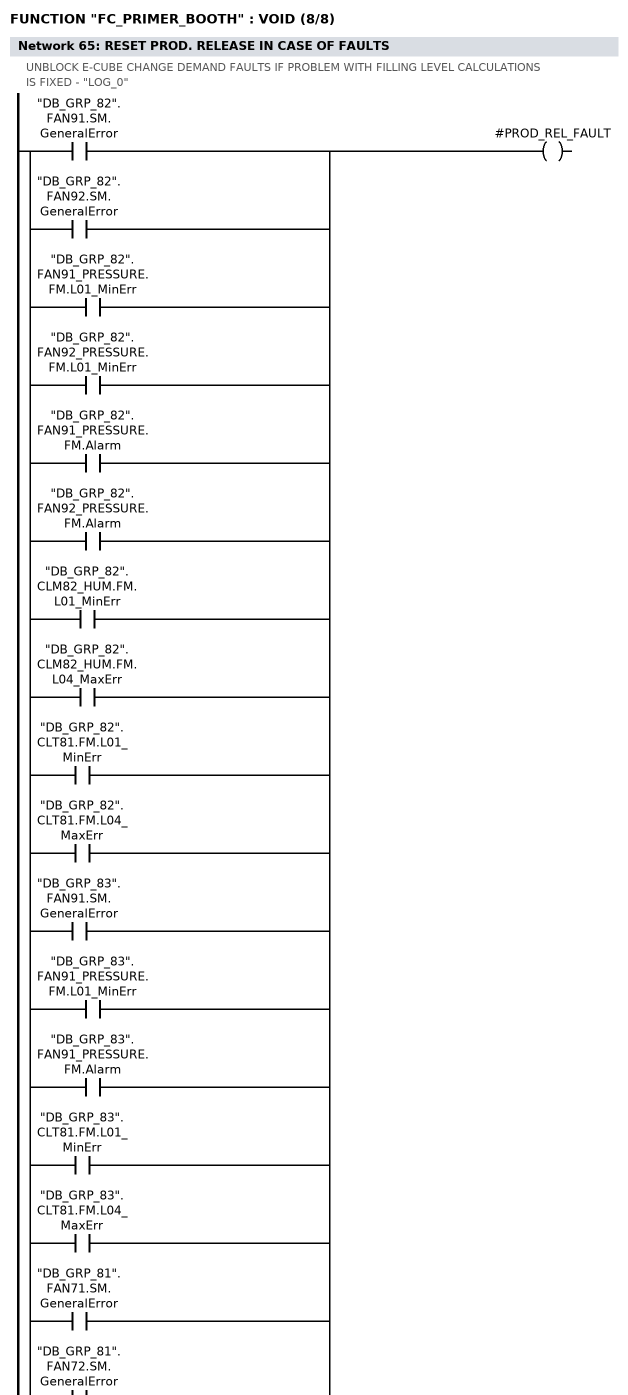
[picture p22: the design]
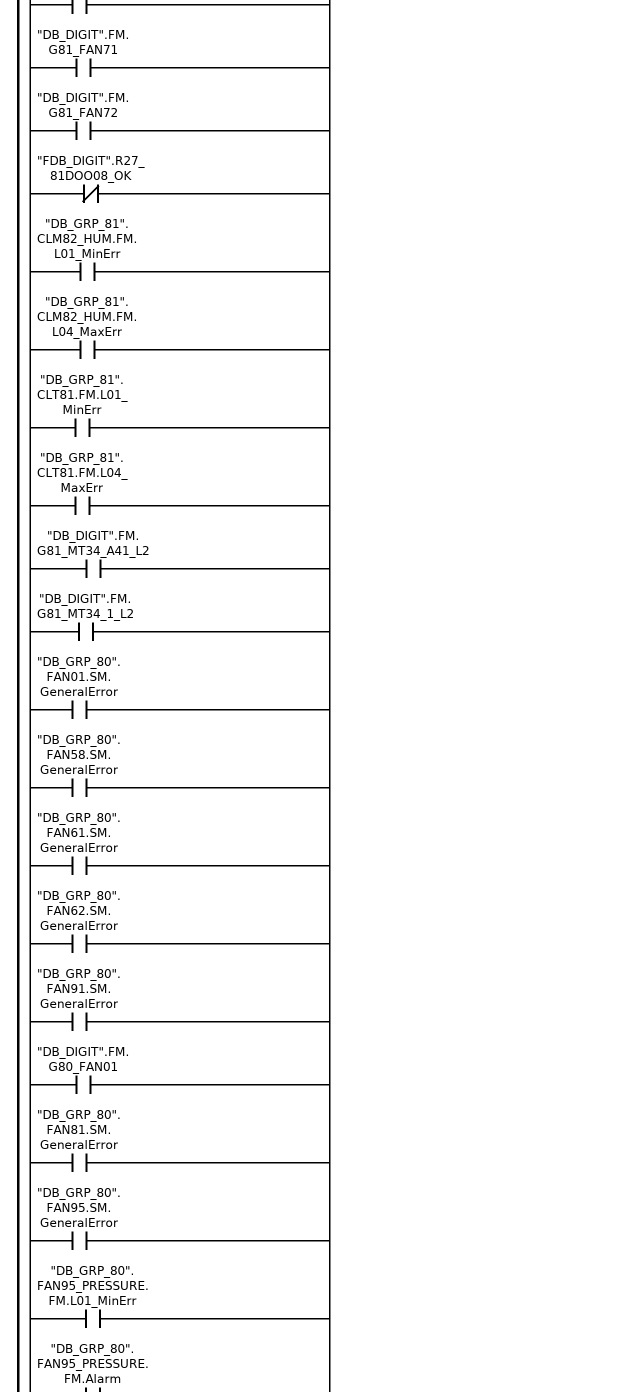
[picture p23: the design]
FUNCTION "FC_PRIMER_BOOTH" : VOID
TITLE =PRIMER BOOTH
{ S7_language := '9(1) Angielski (Stany Zjednoczone)  11.01.2022  09:45:15' }
VERSION : 0.1


VAR_TEMP
  ASU_PREHEAT_TIME_SP : S5TIME ;
  ROLL_UP_ENT_DOOR : BOOL ;
  PURGING_TIME_SP : S5TIME ;
  PROD_REL_CONV : BOOL ;
  PROD_REL_FAULT : BOOL ;
  PREPURGING_ON : BOOL ;
  FOLLOW_UP_PURGING_ON : BOOL ;
  F_UP_PRUGING_TIME_SP : S5TIME ;
  H_81CLM82_HUM_SWP : REAL ;
  H_81CLM82_DEHUM_SWP : REAL ;
  T_81CLT81_COOL_SWP : REAL ;
  T_81CLT81_HEAT_SWP : REAL ;
END_VAR
BEGIN
NETWORK
TITLE =PRIMER BOOTH ON
//********************************************************************************
//
//                         PRIMER BOOTH START / STOP
//
//********************************************************************************
//
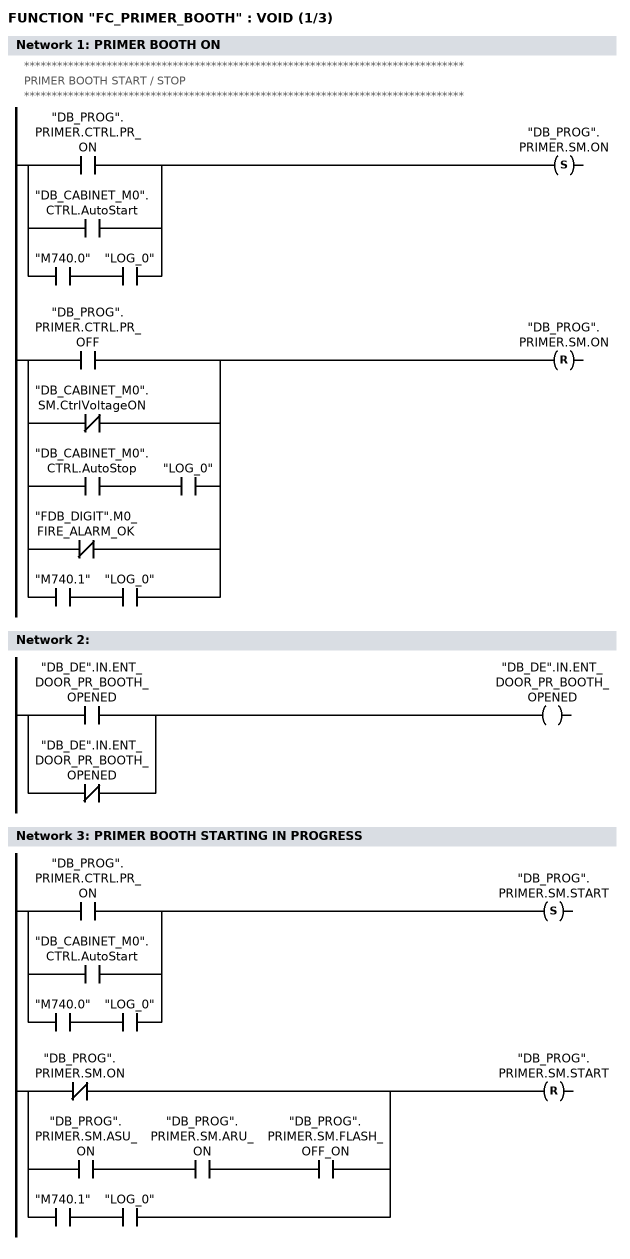
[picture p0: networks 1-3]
      U(    ;
      O     "DB_PROG".PRIMER.CTRL.PR_ON;
      O     "DB_CABINET_M0".CTRL.AutoStart;
      O     ;
      U     "M740.0";
      U     "LOG_0";
      )     ;
      S     "DB_PROG".PRIMER.SM.ON;
      U(    ;
      O     "DB_PROG".PRIMER.CTRL.PR_OFF;
      ON    "DB_CABINET_M0".SM.CtrlVoltageON;
      O     ;
      U     "DB_CABINET_M0".CTRL.AutoStop;
      U     "LOG_0";
      ON    "FDB_DIGIT".M0_FIRE_ALARM_OK;
      O     ;
      U     "M740.1";
      U     "LOG_0";
      )     ;
      R     "DB_PROG".PRIMER.SM.ON;
      NOP   0;
NETWORK
TITLE =

      O     "DB_DE".IN.ENT_DOOR_PR_BOOTH_OPENED;
      ON    "DB_DE".IN.ENT_DOOR_PR_BOOTH_OPENED;
      =     "DB_DE".IN.ENT_DOOR_PR_BOOTH_OPENED;
NETWORK
TITLE =PRIMER BOOTH STARTING IN PROGRESS

      U(    ;
      O     "DB_PROG".PRIMER.CTRL.PR_ON;
      O     "DB_CABINET_M0".CTRL.AutoStart;
      O     ;
      U     "M740.0";
      U     "LOG_0";
      )     ;
      S     "DB_PROG".PRIMER.SM.START;
      U(    ;
      ON    "DB_PROG".PRIMER.SM.ON;
      O     ;
      U     "DB_PROG".PRIMER.SM.ASU_ON;
      U     "DB_PROG".PRIMER.SM.ARU_ON;
      U     "DB_PROG".PRIMER.SM.FLASH_OFF_ON;
      O     ;
      U     "M740.1";
      U     "LOG_0";
      )     ;
      R     "DB_PROG".PRIMER.SM.START;
      NOP   0;
NETWORK
TITLE =PRIMER BOOTH STOPPING IN PROGRESS

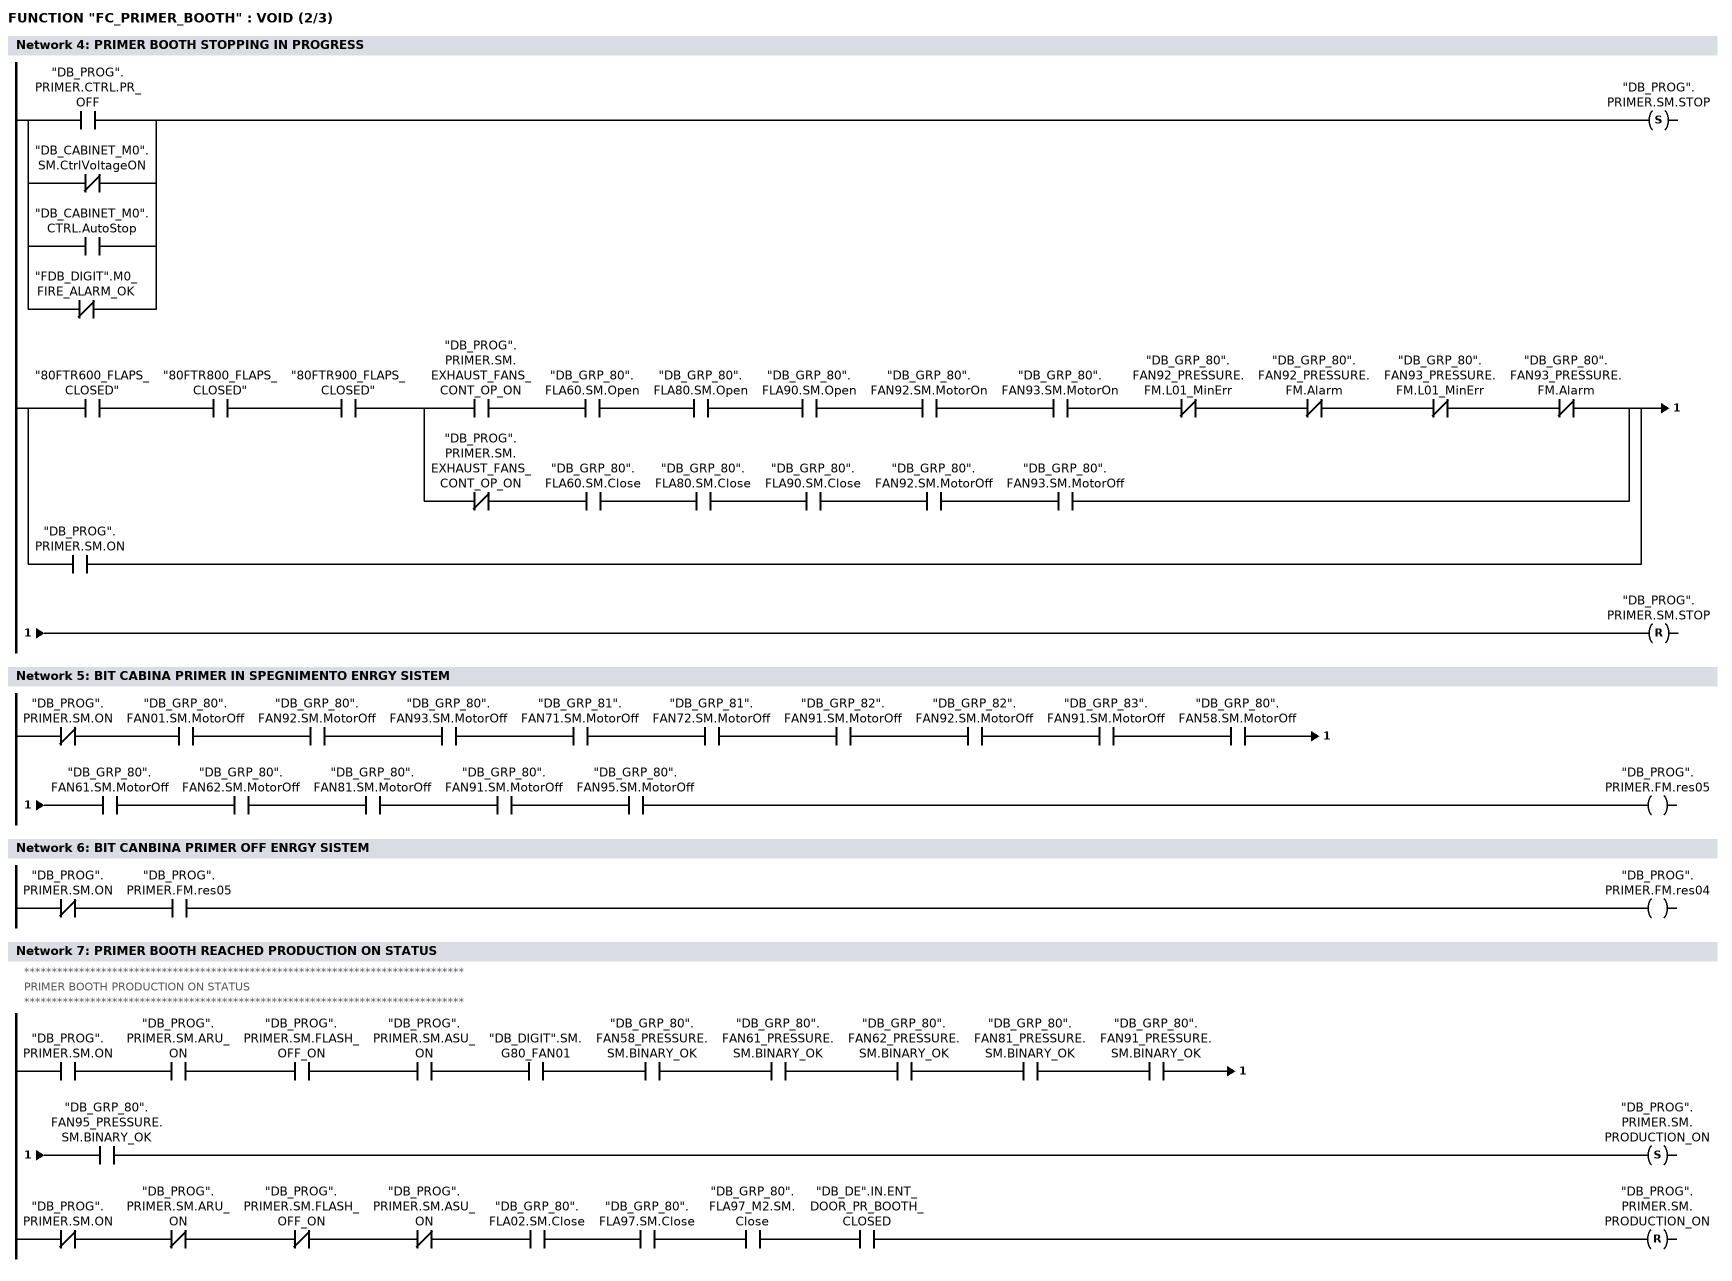
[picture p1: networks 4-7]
      U(    ;
      O     "DB_PROG".PRIMER.CTRL.PR_OFF;
      ON    "DB_CABINET_M0".SM.CtrlVoltageON;
      O     "DB_CABINET_M0".CTRL.AutoStop;
      ON    "FDB_DIGIT".M0_FIRE_ALARM_OK;
      )     ;
      S     "DB_PROG".PRIMER.SM.STOP;
      U(    ;
      U     "80FTR600_FLAPS_CLOSED";
      U     "80FTR800_FLAPS_CLOSED";
      U     "80FTR900_FLAPS_CLOSED";
      U(    ;
      U     "DB_PROG".PRIMER.SM.EXHAUST_FANS_CONT_OP_ON;
      U     "DB_GRP_80".FLA60.SM.Open;
      U     "DB_GRP_80".FLA80.SM.Open;
      U     "DB_GRP_80".FLA90.SM.Open;
      U     "DB_GRP_80".FAN92.SM.MotorOn;
      U     "DB_GRP_80".FAN93.SM.MotorOn;
      UN    "DB_GRP_80".FAN92_PRESSURE.FM.L01_MinErr;
      UN    "DB_GRP_80".FAN92_PRESSURE.FM.Alarm;
      UN    "DB_GRP_80".FAN93_PRESSURE.FM.L01_MinErr;
      UN    "DB_GRP_80".FAN93_PRESSURE.FM.Alarm;
      O     ;
      UN    "DB_PROG".PRIMER.SM.EXHAUST_FANS_CONT_OP_ON;
      U     "DB_GRP_80".FLA60.SM.Close;
      U     "DB_GRP_80".FLA80.SM.Close;
      U     "DB_GRP_80".FLA90.SM.Close;
      U     "DB_GRP_80".FAN92.SM.MotorOff;
      U     "DB_GRP_80".FAN93.SM.MotorOff;
      )     ;
      O     "DB_PROG".PRIMER.SM.ON;
      )     ;
      R     "DB_PROG".PRIMER.SM.STOP;
      NOP   0;
NETWORK
TITLE =BIT CABINA PRIMER IN SPEGNIMENTO ENRGY SISTEM

      UN    "DB_PROG".PRIMER.SM.ON;
      U     "DB_GRP_80".FAN01.SM.MotorOff;
      U     "DB_GRP_80".FAN92.SM.MotorOff;
      U     "DB_GRP_80".FAN93.SM.MotorOff;
      U     "DB_GRP_81".FAN71.SM.MotorOff;
      U     "DB_GRP_81".FAN72.SM.MotorOff;
      U     "DB_GRP_82".FAN91.SM.MotorOff;
      U     "DB_GRP_82".FAN92.SM.MotorOff;
      U     "DB_GRP_83".FAN91.SM.MotorOff;
      U     "DB_GRP_80".FAN58.SM.MotorOff;
      U     "DB_GRP_80".FAN61.SM.MotorOff;
      U     "DB_GRP_80".FAN62.SM.MotorOff;
      U     "DB_GRP_80".FAN81.SM.MotorOff;
      U     "DB_GRP_80".FAN91.SM.MotorOff;
      U     "DB_GRP_80".FAN95.SM.MotorOff;
      =     "DB_PROG".PRIMER.FM.res05;
NETWORK
TITLE =BIT CANBINA PRIMER OFF ENRGY SISTEM

      UN    "DB_PROG".PRIMER.SM.ON;
      U     "DB_PROG".PRIMER.FM.res05;
      =     "DB_PROG".PRIMER.FM.res04;
NETWORK
TITLE =PRIMER BOOTH REACHED PRODUCTION ON STATUS
//********************************************************************************
//
//                      PRIMER BOOTH PRODUCTION ON STATUS
//
//********************************************************************************
//
      U     "DB_PROG".PRIMER.SM.ON;
      U     "DB_PROG".PRIMER.SM.ARU_ON;
      U     "DB_PROG".PRIMER.SM.FLASH_OFF_ON;
      U     "DB_PROG".PRIMER.SM.ASU_ON;
      U     "DB_DIGIT".SM.G80_FAN01;
      U     "DB_GRP_80".FAN58_PRESSURE.SM.BINARY_OK;
      U     "DB_GRP_80".FAN61_PRESSURE.SM.BINARY_OK;
      U     "DB_GRP_80".FAN62_PRESSURE.SM.BINARY_OK;
      U     "DB_GRP_80".FAN81_PRESSURE.SM.BINARY_OK;
      U     "DB_GRP_80".FAN91_PRESSURE.SM.BINARY_OK;
      U     "DB_GRP_80".FAN95_PRESSURE.SM.BINARY_OK;
      S     "DB_PROG".PRIMER.SM.PRODUCTION_ON;
      UN    "DB_PROG".PRIMER.SM.ON;
      UN    "DB_PROG".PRIMER.SM.ARU_ON;
      UN    "DB_PROG".PRIMER.SM.FLASH_OFF_ON;
      UN    "DB_PROG".PRIMER.SM.ASU_ON;
      U     "DB_GRP_80".FLA02.SM.Close;
      U     "DB_GRP_80".FLA97.SM.Close;
      U     "DB_GRP_80".FLA97_M2.SM.Close;
      U     "DB_DE".IN.ENT_DOOR_PR_BOOTH_CLOSED;
      R     "DB_PROG".PRIMER.SM.PRODUCTION_ON;
      NOP   0;
NETWORK
TITLE =E-CUBE STATIONS ARE READY TO START PRIMER BOOTH
//********************************************************************************
//
//                                 E-CUBES
//
//********************************************************************************
//
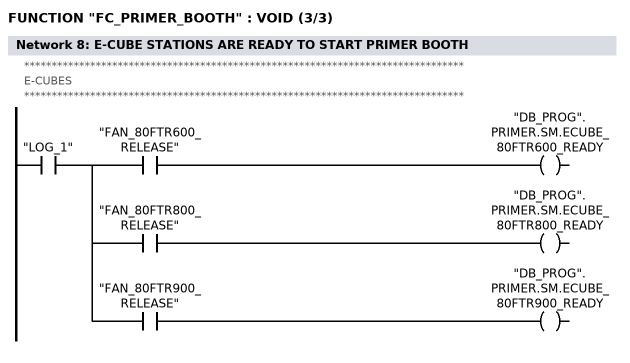
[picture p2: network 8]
      U     "LOG_1";
      =     L     26.0;
      U     L     26.0;
      U     "FAN_80FTR600_RELEASE";
      =     "DB_PROG".PRIMER.SM.ECUBE_80FTR600_READY;
      U     L     26.0;
      U     "FAN_80FTR800_RELEASE";
      =     "DB_PROG".PRIMER.SM.ECUBE_80FTR800_READY;
      U     L     26.0;
      U     "FAN_80FTR900_RELEASE";
      =     "DB_PROG".PRIMER.SM.ECUBE_80FTR900_READY;
NETWORK
TITLE =OPEN/CLOSE E-CUBE FLAPS

      U     "DB_PROG".PRIMER.SM.ON;
      S     "ECUBE_OPEN_FLAPS";
      U(    ;
      U(    ;
      U     "DB_PROG".PRIMER.SM.STOP;
      U(    ;
      O     "DB_GRP_80".FLA02.SM.Close;
      O     "LOG_1";
      )     ;
      U(    ;
      U     "DB_GRP_80".FLA97.SM.Close;
      U     "DB_GRP_80".FLA97_M2.SM.Close;
      O     "LOG_1";
      )     ;
      U(    ;
      O     "DB_DE".IN.ENT_DOOR_PR_BOOTH_CLOSED;
      O     "LOG_1";
      )     ;
      S     "PRBoothProd_off";
      UN    "ECUBE_OPEN_FLAPS";
      R     "PRBoothProd_off";
      U     "PRBoothProd_off";
      )     ;
      UN    "DB_PROG".PRIMER.SM.ON;
      L     S5T#3M;
      SE    "T_PR_PROD_OFF";
      U(    ;
      ON    "ECUBE_OPEN_FLAPS";
      O     "DB_PROG".PRIMER.SM.ON;
      )     ;
      R     "T_PR_PROD_OFF";
      NOP   0;
      NOP   0;
      U     "T_PR_PROD_OFF";
      )     ;
      R     "ECUBE_OPEN_FLAPS";
      NOP   0;
NETWORK
TITLE =E-CUBE STATIONS FLAPS CLOSED

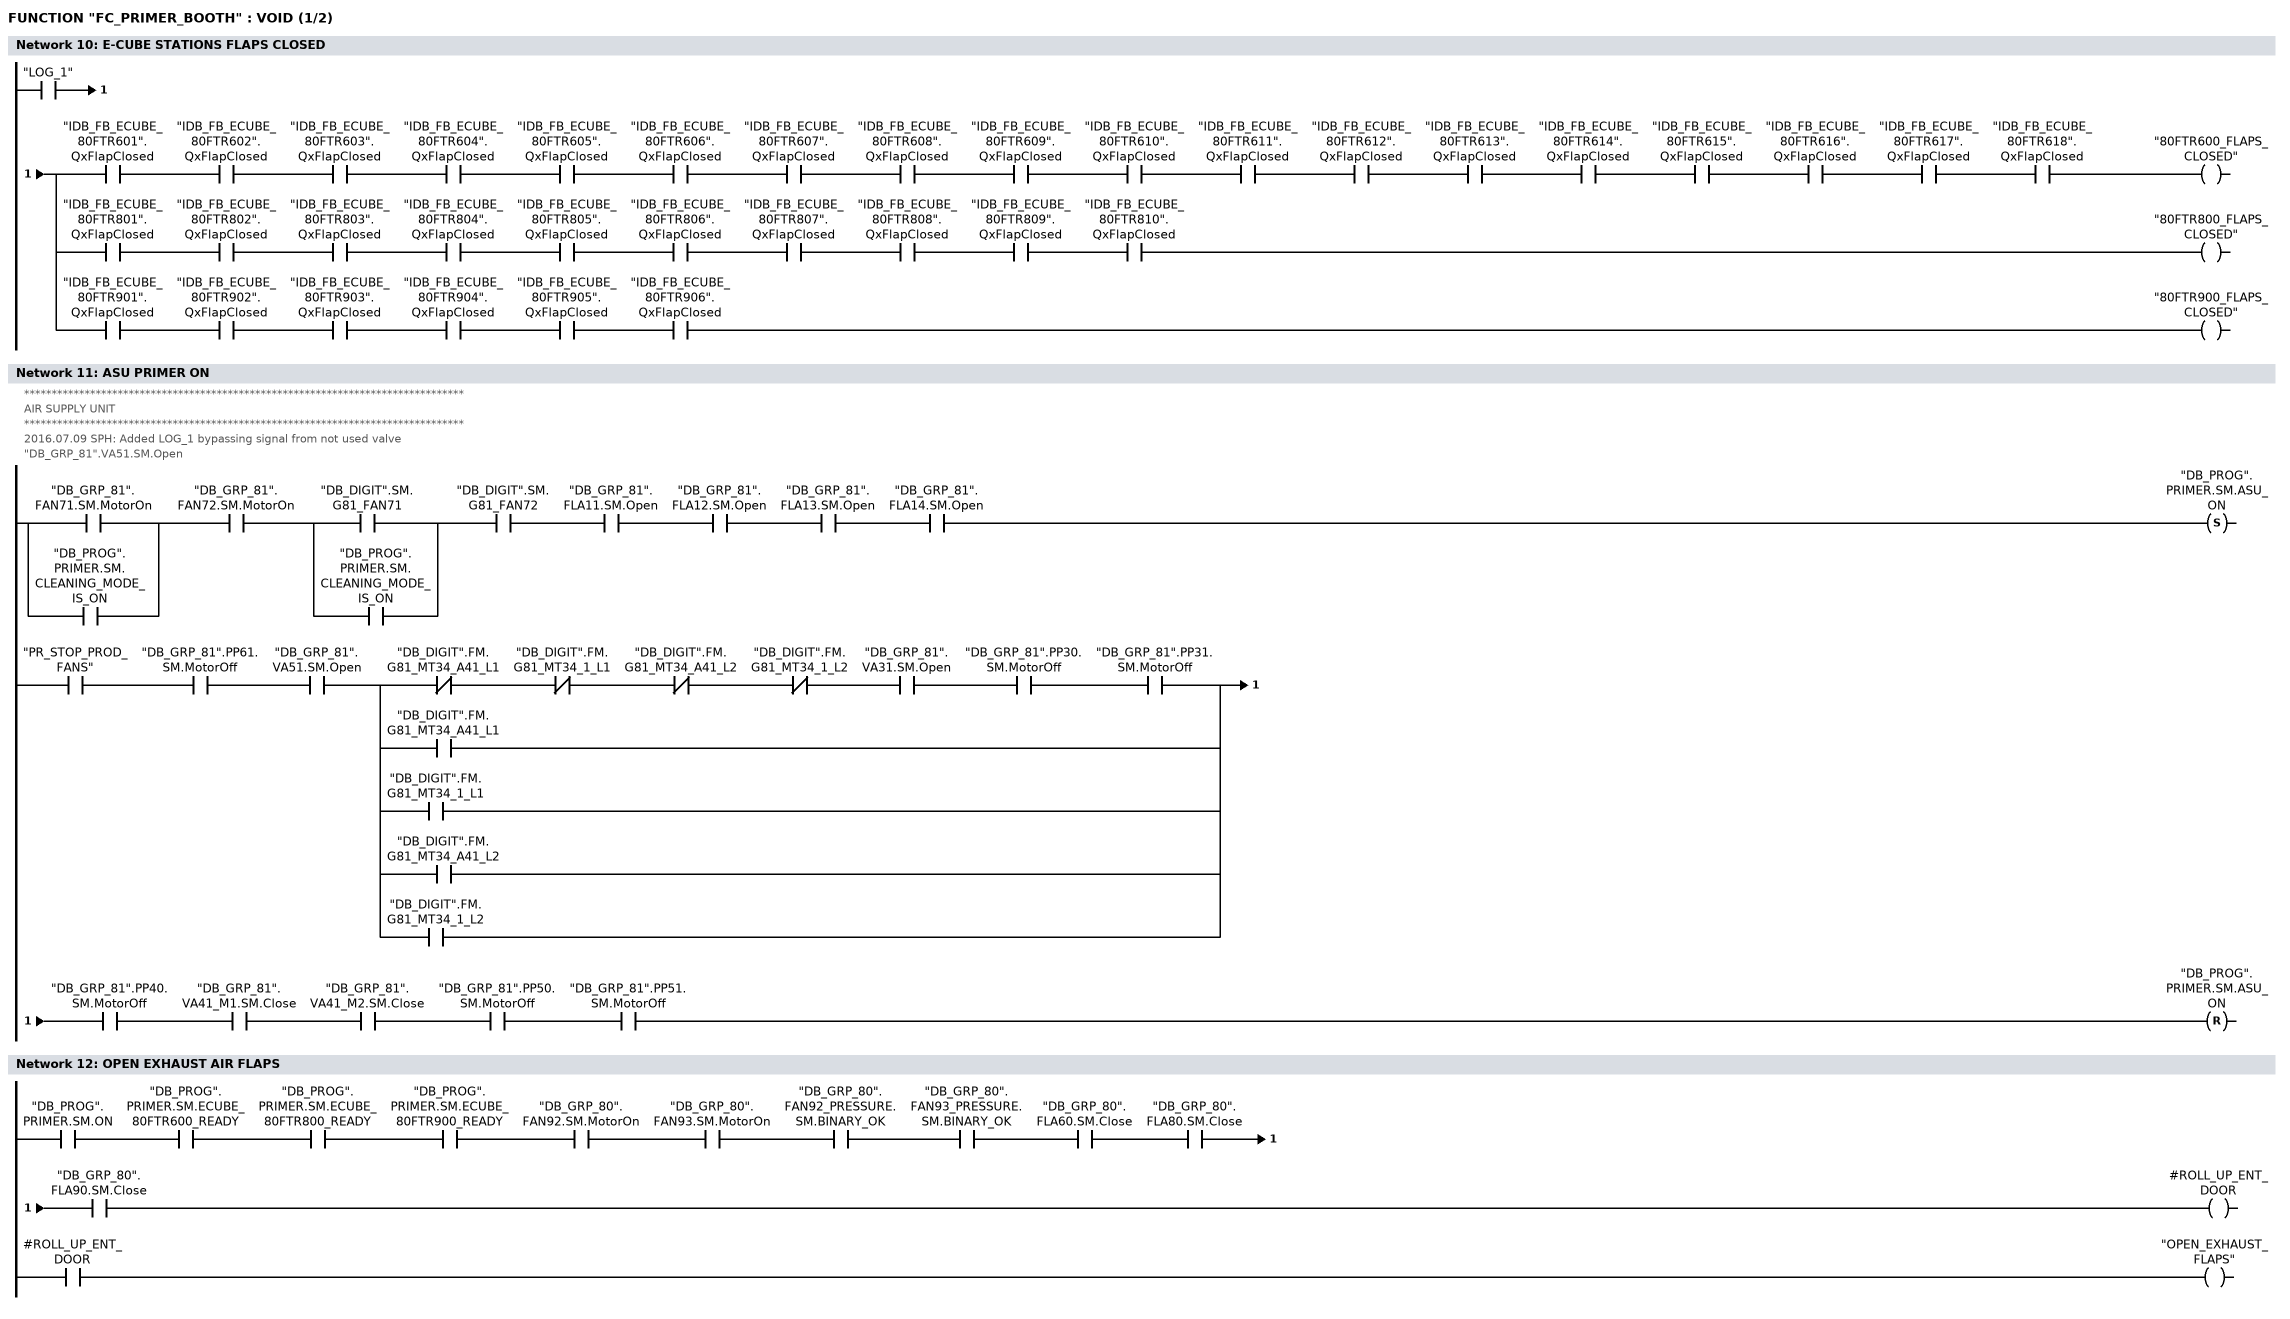
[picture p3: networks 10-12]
      U     "LOG_1";
      =     L     26.0;
      U     L     26.0;
      U     "IDB_FB_ECUBE_80FTR601".QxFlapClosed;
      U     "IDB_FB_ECUBE_80FTR602".QxFlapClosed;
      U     "IDB_FB_ECUBE_80FTR603".QxFlapClosed;
      U     "IDB_FB_ECUBE_80FTR604".QxFlapClosed;
      U     "IDB_FB_ECUBE_80FTR605".QxFlapClosed;
      U     "IDB_FB_ECUBE_80FTR606".QxFlapClosed;
      U     "IDB_FB_ECUBE_80FTR607".QxFlapClosed;
      U     "IDB_FB_ECUBE_80FTR608".QxFlapClosed;
      U     "IDB_FB_ECUBE_80FTR609".QxFlapClosed;
      U     "IDB_FB_ECUBE_80FTR610".QxFlapClosed;
      U     "IDB_FB_ECUBE_80FTR611".QxFlapClosed;
      U     "IDB_FB_ECUBE_80FTR612".QxFlapClosed;
      U     "IDB_FB_ECUBE_80FTR613".QxFlapClosed;
      U     "IDB_FB_ECUBE_80FTR614".QxFlapClosed;
      U     "IDB_FB_ECUBE_80FTR615".QxFlapClosed;
      U     "IDB_FB_ECUBE_80FTR616".QxFlapClosed;
      U     "IDB_FB_ECUBE_80FTR617".QxFlapClosed;
      U     "IDB_FB_ECUBE_80FTR618".QxFlapClosed;
      =     "80FTR600_FLAPS_CLOSED";
      U     L     26.0;
      U     "IDB_FB_ECUBE_80FTR801".QxFlapClosed;
      U     "IDB_FB_ECUBE_80FTR802".QxFlapClosed;
      U     "IDB_FB_ECUBE_80FTR803".QxFlapClosed;
      U     "IDB_FB_ECUBE_80FTR804".QxFlapClosed;
      U     "IDB_FB_ECUBE_80FTR805".QxFlapClosed;
      U     "IDB_FB_ECUBE_80FTR806".QxFlapClosed;
      U     "IDB_FB_ECUBE_80FTR807".QxFlapClosed;
      U     "IDB_FB_ECUBE_80FTR808".QxFlapClosed;
      U     "IDB_FB_ECUBE_80FTR809".QxFlapClosed;
      U     "IDB_FB_ECUBE_80FTR810".QxFlapClosed;
      =     "80FTR800_FLAPS_CLOSED";
      U     L     26.0;
      U     "IDB_FB_ECUBE_80FTR901".QxFlapClosed;
      U     "IDB_FB_ECUBE_80FTR902".QxFlapClosed;
      U     "IDB_FB_ECUBE_80FTR903".QxFlapClosed;
      U     "IDB_FB_ECUBE_80FTR904".QxFlapClosed;
      U     "IDB_FB_ECUBE_80FTR905".QxFlapClosed;
      U     "IDB_FB_ECUBE_80FTR906".QxFlapClosed;
      =     "80FTR900_FLAPS_CLOSED";
NETWORK
TITLE =ASU PRIMER ON
//********************************************************************************
//
//                                  AIR SUPPLY UNIT
//
//********************************************************************************
//
//2016.07.09 SPH: Added LOG_1 bypassing signal from not used valve
//"DB_GRP_81".VA51.SM.Open
      U(    ;
      O     "DB_GRP_81".FAN71.SM.MotorOn;
      O     "DB_PROG".PRIMER.SM.CLEANING_MODE_IS_ON;
      )     ;
      U     "DB_GRP_81".FAN72.SM.MotorOn;
      U(    ;
      O     "DB_DIGIT".SM.G81_FAN71;
      O     "DB_PROG".PRIMER.SM.CLEANING_MODE_IS_ON;
      )     ;
      U     "DB_DIGIT".SM.G81_FAN72;
      U     "DB_GRP_81".FLA11.SM.Open;
      U     "DB_GRP_81".FLA12.SM.Open;
      U     "DB_GRP_81".FLA13.SM.Open;
      U     "DB_GRP_81".FLA14.SM.Open;
      S     "DB_PROG".PRIMER.SM.ASU_ON;
      U     "PR_STOP_PROD_FANS";
      U     "DB_GRP_81".PP61.SM.MotorOff;
      U     "DB_GRP_81".VA51.SM.Open;
      U(    ;
      UN    "DB_DIGIT".FM.G81_MT34_A41_L1;
      UN    "DB_DIGIT".FM.G81_MT34_1_L1;
      UN    "DB_DIGIT".FM.G81_MT34_A41_L2;
      UN    "DB_DIGIT".FM.G81_MT34_1_L2;
      U     "DB_GRP_81".VA31.SM.Open;
      U     "DB_GRP_81".PP30.SM.MotorOff;
      U     "DB_GRP_81".PP31.SM.MotorOff;
      O     "DB_DIGIT".FM.G81_MT34_A41_L1;
      O     "DB_DIGIT".FM.G81_MT34_1_L1;
      O     "DB_DIGIT".FM.G81_MT34_A41_L2;
      O     "DB_DIGIT".FM.G81_MT34_1_L2;
      )     ;
      U     "DB_GRP_81".PP40.SM.MotorOff;
      U     "DB_GRP_81".VA41_M1.SM.Close;
      U     "DB_GRP_81".VA41_M2.SM.Close;
      U     "DB_GRP_81".PP50.SM.MotorOff;
      U     "DB_GRP_81".PP51.SM.MotorOff;
      R     "DB_PROG".PRIMER.SM.ASU_ON;
      NOP   0;
NETWORK
TITLE =OPEN EXHAUST AIR FLAPS

      U     "DB_PROG".PRIMER.SM.ON;
      U     "DB_PROG".PRIMER.SM.ECUBE_80FTR600_READY;
      U     "DB_PROG".PRIMER.SM.ECUBE_80FTR800_READY;
      U     "DB_PROG".PRIMER.SM.ECUBE_80FTR900_READY;
      U     "DB_GRP_80".FAN92.SM.MotorOn;
      U     "DB_GRP_80".FAN93.SM.MotorOn;
      U     "DB_GRP_80".FAN92_PRESSURE.SM.BINARY_OK;
      U     "DB_GRP_80".FAN93_PRESSURE.SM.BINARY_OK;
      U     "DB_GRP_80".FLA60.SM.Close;
      U     "DB_GRP_80".FLA80.SM.Close;
      U     "DB_GRP_80".FLA90.SM.Close;
      =     #ROLL_UP_ENT_DOOR;
      U     #ROLL_UP_ENT_DOOR;
      =     "OPEN_EXHAUST_FLAPS";
NETWORK
TITLE =CLOSE EXHAUST AIR FLAPS

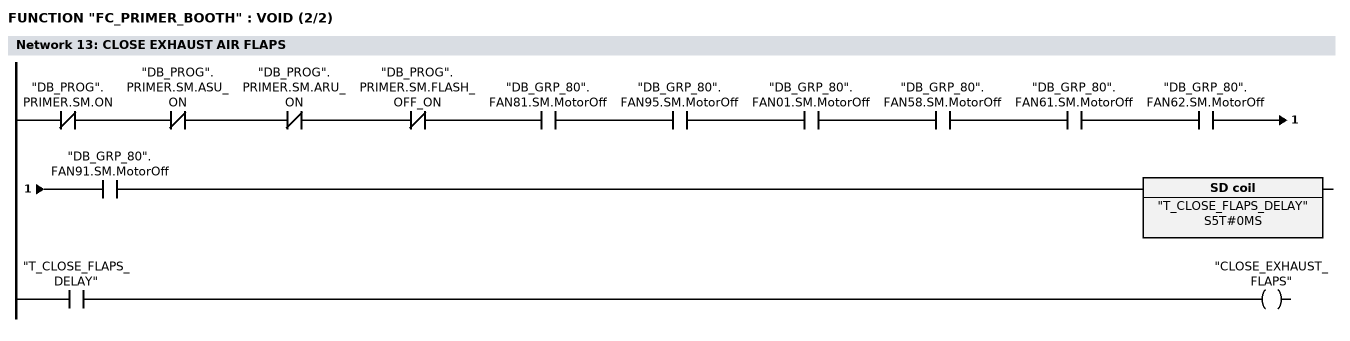
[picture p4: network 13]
      UN    "DB_PROG".PRIMER.SM.ON;
      UN    "DB_PROG".PRIMER.SM.ASU_ON;
      UN    "DB_PROG".PRIMER.SM.ARU_ON;
      UN    "DB_PROG".PRIMER.SM.FLASH_OFF_ON;
      U     "DB_GRP_80".FAN81.SM.MotorOff;
      U     "DB_GRP_80".FAN95.SM.MotorOff;
      U     "DB_GRP_80".FAN01.SM.MotorOff;
      U     "DB_GRP_80".FAN58.SM.MotorOff;
      U     "DB_GRP_80".FAN61.SM.MotorOff;
      U     "DB_GRP_80".FAN62.SM.MotorOff;
      U     "DB_GRP_80".FAN91.SM.MotorOff;
      L     S5T#0MS;
      SE    "T_CLOSE_FLAPS_DELAY";
      NOP   0;
      NOP   0;
      NOP   0;
      U     "T_CLOSE_FLAPS_DELAY";
      =     "CLOSE_EXHAUST_FLAPS";
NETWORK
TITLE =AIR SUPPLY UNIT START PREHEATING IF OUTSIDE TEMP IS LOW

      U(    ;
      U(    ;
      O     "DB_GRP_80".FLA02.SM.Open;
      ON    "DB_GRP_80".FLA02.SM.Open;
      )     ;
      U(    ;
      O     "DB_GRP_80".FLA97.SM.Open;
      ON    "DB_GRP_80".FLA97.SM.Open;
      )     ;
      U(    ;
      O     "DB_GRP_80".FLA97_M2.SM.Open;
      ON    "DB_GRP_80".FLA97_M2.SM.Open;
      )     ;
      U     "DB_DE".IN.ENT_DOOR_PR_BOOTH_OPENED;
      L     S5T#20S;
      SE    "T_ASU_START_DELAY";
      NOP   0;
      NOP   0;
      NOP   0;
      U     "T_ASU_START_DELAY";
      )     ;
      FP    "CHECK_OUTSIDE_TEMP_PE";
      U(    ;
      L     "DB_GRP_81".CLM10_TEMP.PV.AV;
      L     1.000000e+001;
      <R    ;
      )     ;
      S     "81PP30_PP31_START";
      U(    ;
      O     "DB_PROG".PRIMER.SM.ASU_REGULATION_ON;
      ON    "DB_PROG".PRIMER.SM.ON;
      )     ;
      R     "81PP30_PP31_START";
      NOP   0;
NETWORK
TITLE =AIR SUPPLY UNIT PRIMER AIR PREHEATING TIMER SETPOINT

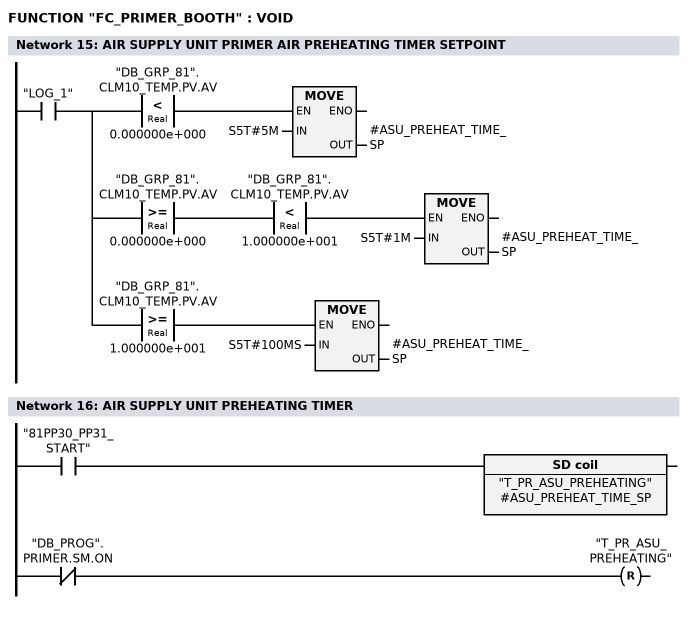
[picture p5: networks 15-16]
      U     "LOG_1";
      =     L     26.0;
      U     L     26.0;
      U(    ;
      L     "DB_GRP_81".CLM10_TEMP.PV.AV;
      L     0.000000e+000;
      <R    ;
      )     ;
      SPBNB _001;
      L     S5T#5M;
      T     #ASU_PREHEAT_TIME_SP;
_001: NOP   0;
      U     L     26.0;
      U(    ;
      L     "DB_GRP_81".CLM10_TEMP.PV.AV;
      L     0.000000e+000;
      >=R   ;
      )     ;
      U(    ;
      L     "DB_GRP_81".CLM10_TEMP.PV.AV;
      L     1.000000e+001;
      <R    ;
      )     ;
      SPBNB _002;
      L     S5T#1M;
      T     #ASU_PREHEAT_TIME_SP;
_002: NOP   0;
      U     L     26.0;
      U(    ;
      L     "DB_GRP_81".CLM10_TEMP.PV.AV;
      L     1.000000e+001;
      >=R   ;
      )     ;
      SPBNB _003;
      L     S5T#100MS;
      T     #ASU_PREHEAT_TIME_SP;
_003: NOP   0;
NETWORK
TITLE =AIR SUPPLY UNIT PREHEATING TIMER

      U     "81PP30_PP31_START";
      L     #ASU_PREHEAT_TIME_SP;
      SE    "T_PR_ASU_PREHEATING";
      UN    "DB_PROG".PRIMER.SM.ON;
      R     "T_PR_ASU_PREHEATING";
      NOP   0;
      NOP   0;
      NOP   0;
NETWORK
TITLE =OPEN AIR SUPPLY UNIT FLAPS

      U(    ;
      U     "81PP30_PP31_START";
      U     "T_PR_ASU_PREHEATING";
      O(    ;
      U     "T_ASU_START_DELAY";
      UN    "81PP30_PP31_START";
      L     S5T#100MS;
      SE    "T_ASU_FLAPS_OPEN_DELAY";
      NOP   0;
      NOP   0;
      NOP   0;
      U     "T_ASU_FLAPS_OPEN_DELAY";
      )     ;
      )     ;
      U     "DB_PROG".PRIMER.SM.ON;
      U     "DB_GRP_80".FLA60.SM.Close;
      U     "DB_GRP_80".FLA80.SM.Close;
      U     "DB_GRP_80".FLA90.SM.Close;
      U(    ;
      O     "DB_GRP_80".FLA02.SM.Open;
      ON    "DB_GRP_80".FLA02.SM.Open;
      )     ;
      U(    ;
      O     "DB_GRP_80".FLA97.SM.Open;
      ON    "DB_GRP_80".FLA97.SM.Open;
      )     ;
      U(    ;
      O     "DB_GRP_80".FLA97_M2.SM.Open;
      ON    "DB_GRP_80".FLA97_M2.SM.Open;
      )     ;
      U     "DB_DE".IN.ENT_DOOR_PR_BOOTH_OPENED;
      =     "OPEN_ASU_FLAPS";
NETWORK
TITLE =CLOSE AIR SUPPLY UNIT FLAPS

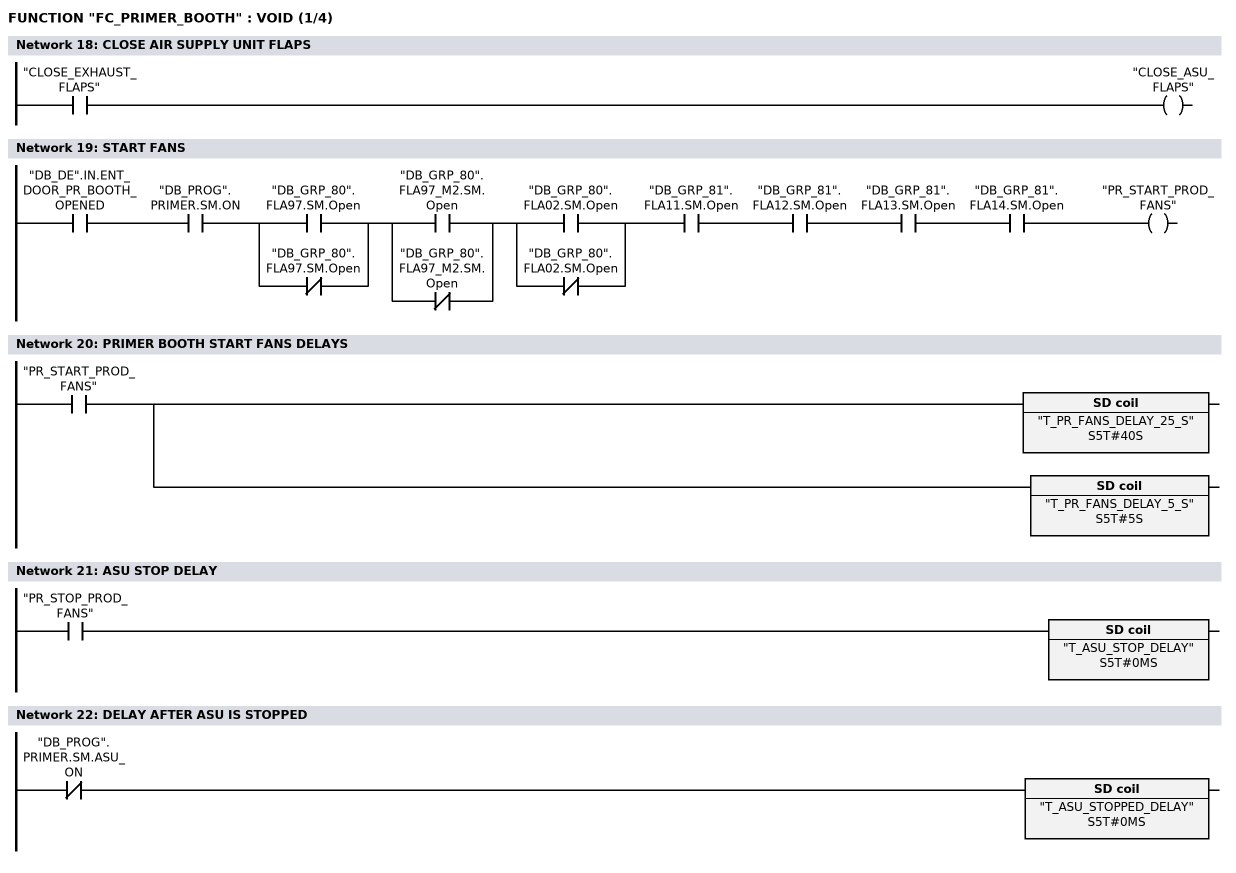
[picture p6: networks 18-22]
      U     "CLOSE_EXHAUST_FLAPS";
      =     "CLOSE_ASU_FLAPS";
NETWORK
TITLE =START FANS

      U     "DB_DE".IN.ENT_DOOR_PR_BOOTH_OPENED;
      U     "DB_PROG".PRIMER.SM.ON;
      U(    ;
      O     "DB_GRP_80".FLA97.SM.Open;
      ON    "DB_GRP_80".FLA97.SM.Open;
      )     ;
      U(    ;
      O     "DB_GRP_80".FLA97_M2.SM.Open;
      ON    "DB_GRP_80".FLA97_M2.SM.Open;
      )     ;
      U(    ;
      O     "DB_GRP_80".FLA02.SM.Open;
      ON    "DB_GRP_80".FLA02.SM.Open;
      )     ;
      U     "DB_GRP_81".FLA11.SM.Open;
      U     "DB_GRP_81".FLA12.SM.Open;
      U     "DB_GRP_81".FLA13.SM.Open;
      U     "DB_GRP_81".FLA14.SM.Open;
      =     "PR_START_PROD_FANS";
NETWORK
TITLE =PRIMER BOOTH START FANS DELAYS

      U     "PR_START_PROD_FANS";
      =     L     26.0;
      U     L     26.0;
      L     S5T#40S;
      SE    "T_PR_FANS_DELAY_25_S";
      NOP   0;
      NOP   0;
      NOP   0;
      NOP   0;
      U     L     26.0;
      L     S5T#5S;
      SE    "T_PR_FANS_DELAY_5_S";
      NOP   0;
      NOP   0;
      NOP   0;
      NOP   0;
NETWORK
TITLE =ASU STOP DELAY

      U     "PR_STOP_PROD_FANS";
      L     S5T#0MS;
      SE    "T_ASU_STOP_DELAY";
      NOP   0;
      NOP   0;
      NOP   0;
      NOP   0;
NETWORK
TITLE =DELAY AFTER ASU IS STOPPED

      UN    "DB_PROG".PRIMER.SM.ASU_ON;
      L     S5T#0MS;
      SE    "T_ASU_STOPPED_DELAY";
      NOP   0;
      NOP   0;
      NOP   0;
      NOP   0;
NETWORK
TITLE =ASU TEMP AND HUMIDITY CONTROL ON
//2016.07.09 SPH: Added LOG_1 bypassing signal from not used valve
//"DB_GRP_81".VA51.SM.Open
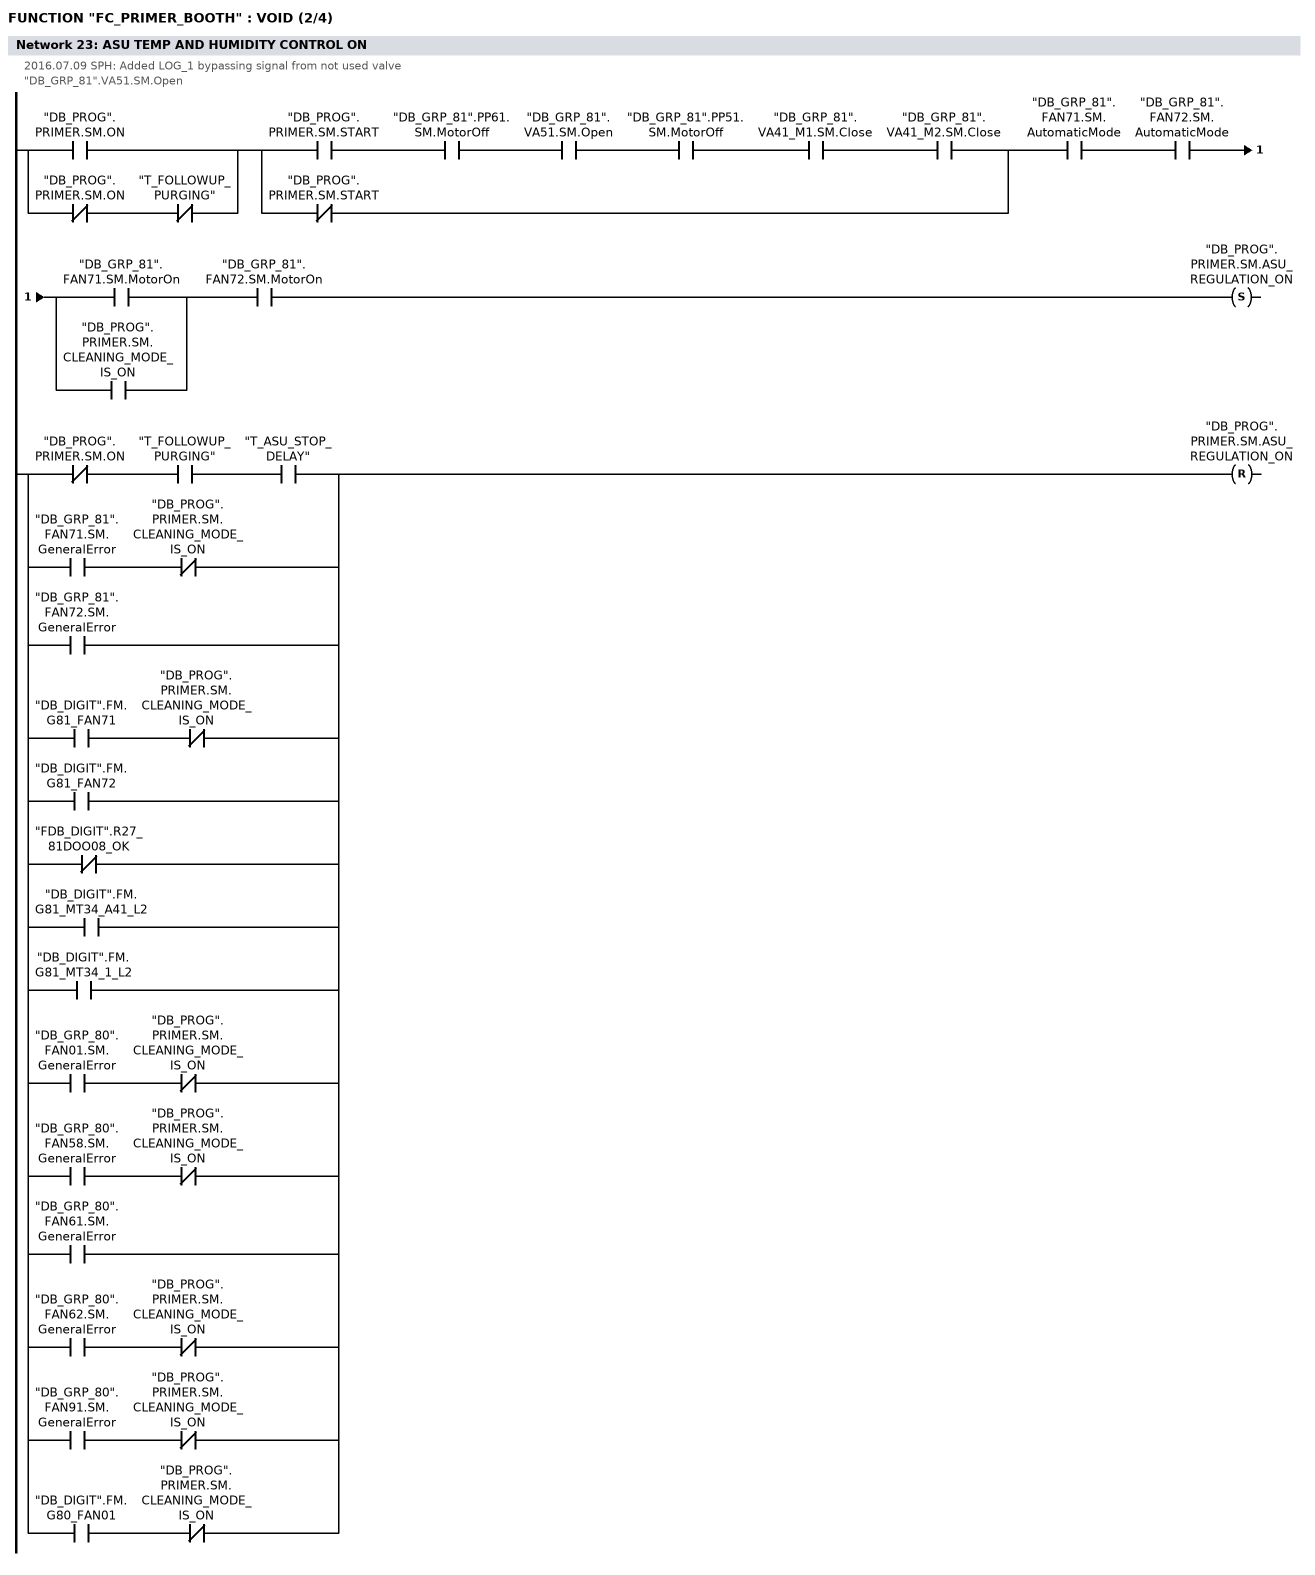
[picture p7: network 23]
      U(    ;
      O     "DB_PROG".PRIMER.SM.ON;
      O     ;
      UN    "DB_PROG".PRIMER.SM.ON;
      UN    "T_FOLLOWUP_PURGING";
      )     ;
      U(    ;
      U     "DB_PROG".PRIMER.SM.START;
      U     "DB_GRP_81".PP61.SM.MotorOff;
      U     "DB_GRP_81".VA51.SM.Open;
      U     "DB_GRP_81".PP51.SM.MotorOff;
      U     "DB_GRP_81".VA41_M1.SM.Close;
      U     "DB_GRP_81".VA41_M2.SM.Close;
      ON    "DB_PROG".PRIMER.SM.START;
      )     ;
      U     "DB_GRP_81".FAN71.SM.AutomaticMode;
      U     "DB_GRP_81".FAN72.SM.AutomaticMode;
      U(    ;
      O     "DB_GRP_81".FAN71.SM.MotorOn;
      O     "DB_PROG".PRIMER.SM.CLEANING_MODE_IS_ON;
      )     ;
      U     "DB_GRP_81".FAN72.SM.MotorOn;
      S     "DB_PROG".PRIMER.SM.ASU_REGULATION_ON;
      U(    ;
      UN    "DB_PROG".PRIMER.SM.ON;
      U     "T_FOLLOWUP_PURGING";
      U     "T_ASU_STOP_DELAY";
      O     ;
      U     "DB_GRP_81".FAN71.SM.GeneralError;
      UN    "DB_PROG".PRIMER.SM.CLEANING_MODE_IS_ON;
      O     "DB_GRP_81".FAN72.SM.GeneralError;
      O     ;
      U     "DB_DIGIT".FM.G81_FAN71;
      UN    "DB_PROG".PRIMER.SM.CLEANING_MODE_IS_ON;
      O     "DB_DIGIT".FM.G81_FAN72;
      ON    "FDB_DIGIT".R27_81DOO08_OK;
      O     "DB_DIGIT".FM.G81_MT34_A41_L2;
      O     "DB_DIGIT".FM.G81_MT34_1_L2;
      O     ;
      U     "DB_GRP_80".FAN01.SM.GeneralError;
      UN    "DB_PROG".PRIMER.SM.CLEANING_MODE_IS_ON;
      O     ;
      U     "DB_GRP_80".FAN58.SM.GeneralError;
      UN    "DB_PROG".PRIMER.SM.CLEANING_MODE_IS_ON;
      O     "DB_GRP_80".FAN61.SM.GeneralError;
      O     ;
      U     "DB_GRP_80".FAN62.SM.GeneralError;
      UN    "DB_PROG".PRIMER.SM.CLEANING_MODE_IS_ON;
      O     ;
      U     "DB_GRP_80".FAN91.SM.GeneralError;
      UN    "DB_PROG".PRIMER.SM.CLEANING_MODE_IS_ON;
      O     ;
      U     "DB_DIGIT".FM.G80_FAN01;
      UN    "DB_PROG".PRIMER.SM.CLEANING_MODE_IS_ON;
      )     ;
      R     "DB_PROG".PRIMER.SM.ASU_REGULATION_ON;
      NOP   0;
NETWORK
TITLE =SET SWITCHING POINTS

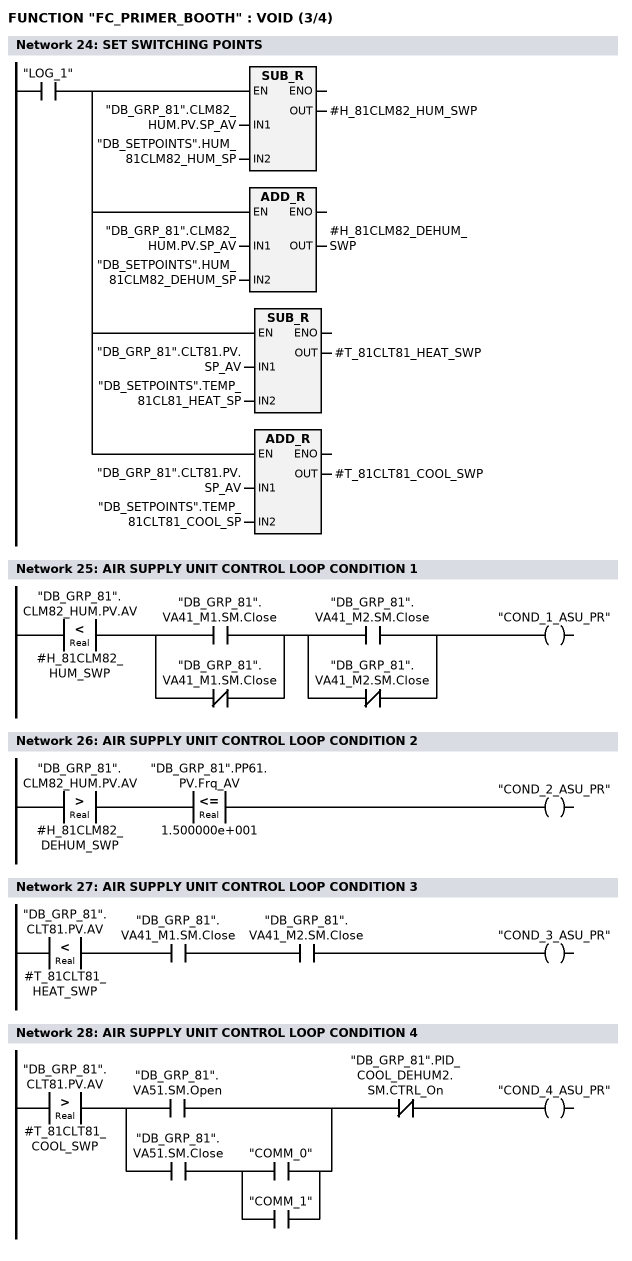
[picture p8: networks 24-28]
      U     "LOG_1";
      =     L     26.0;
      U     L     26.0;
      SPBNB _004;
      L     "DB_GRP_81".CLM82_HUM.PV.SP_AV;
      L     "DB_SETPOINTS".HUM_81CLM82_HUM_SP;
      -R    ;
      T     #H_81CLM82_HUM_SWP;
_004: NOP   0;
      U     L     26.0;
      SPBNB _005;
      L     "DB_GRP_81".CLM82_HUM.PV.SP_AV;
      L     "DB_SETPOINTS".HUM_81CLM82_DEHUM_SP;
      +R    ;
      T     #H_81CLM82_DEHUM_SWP;
_005: NOP   0;
      U     L     26.0;
      SPBNB _006;
      L     "DB_GRP_81".CLT81.PV.SP_AV;
      L     "DB_SETPOINTS".TEMP_81CL81_HEAT_SP;
      -R    ;
      T     #T_81CLT81_HEAT_SWP;
_006: NOP   0;
      U     L     26.0;
      SPBNB _007;
      L     "DB_GRP_81".CLT81.PV.SP_AV;
      L     "DB_SETPOINTS".TEMP_81CLT81_COOL_SP;
      +R    ;
      T     #T_81CLT81_COOL_SWP;
_007: NOP   0;
NETWORK
TITLE =AIR SUPPLY UNIT CONTROL LOOP CONDITION 1

      U(    ;
      L     "DB_GRP_81".CLM82_HUM.PV.AV;
      L     #H_81CLM82_HUM_SWP;
      <R    ;
      )     ;
      U(    ;
      O     "DB_GRP_81".VA41_M1.SM.Close;
      ON    "DB_GRP_81".VA41_M1.SM.Close;
      )     ;
      U(    ;
      O     "DB_GRP_81".VA41_M2.SM.Close;
      ON    "DB_GRP_81".VA41_M2.SM.Close;
      )     ;
      =     "COND_1_ASU_PR";
NETWORK
TITLE =AIR SUPPLY UNIT CONTROL LOOP CONDITION 2

      U(    ;
      L     "DB_GRP_81".CLM82_HUM.PV.AV;
      L     #H_81CLM82_DEHUM_SWP;
      >R    ;
      )     ;
      U(    ;
      L     "DB_GRP_81".PP61.PV.Frq_AV;
      L     1.500000e+001;
      <=R   ;
      )     ;
      =     "COND_2_ASU_PR";
NETWORK
TITLE =AIR SUPPLY UNIT CONTROL LOOP CONDITION 3

      U(    ;
      L     "DB_GRP_81".CLT81.PV.AV;
      L     #T_81CLT81_HEAT_SWP;
      <R    ;
      )     ;
      U     "DB_GRP_81".VA41_M1.SM.Close;
      U     "DB_GRP_81".VA41_M2.SM.Close;
      =     "COND_3_ASU_PR";
NETWORK
TITLE =AIR SUPPLY UNIT CONTROL LOOP CONDITION 4

      U(    ;
      L     "DB_GRP_81".CLT81.PV.AV;
      L     #T_81CLT81_COOL_SWP;
      >R    ;
      )     ;
      U(    ;
      O     "DB_GRP_81".VA51.SM.Open;
      O     ;
      U     "DB_GRP_81".VA51.SM.Close;
      U(    ;
      O     "COMM_0";
      O     "COMM_1";
      )     ;
      )     ;
      UN    "DB_GRP_81".PID_COOL_DEHUM2.SM.CTRL_On;
      =     "COND_4_ASU_PR";
NETWORK
TITLE =AIR SUPPLY UNIT CONTROL LOOP A COOLING/DEHUMIDIFYING ACTIVE

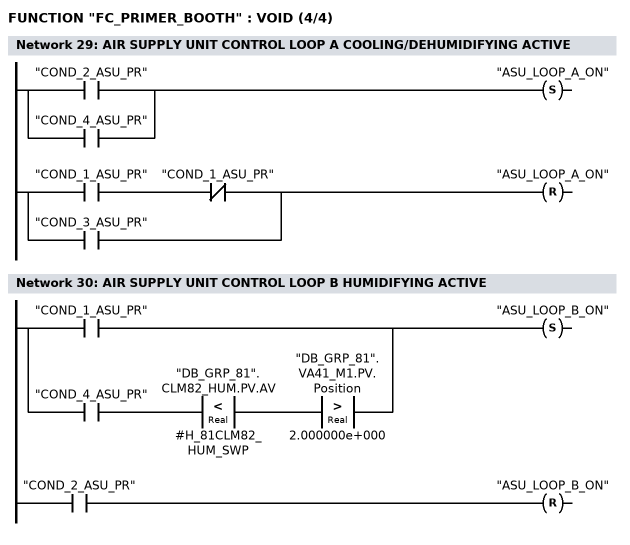
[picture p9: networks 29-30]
      U(    ;
      O     "COND_2_ASU_PR";
      O     "COND_4_ASU_PR";
      )     ;
      S     "ASU_LOOP_A_ON";
      U(    ;
      U     "COND_1_ASU_PR";
      UN    "COND_1_ASU_PR";
      O     "COND_3_ASU_PR";
      )     ;
      R     "ASU_LOOP_A_ON";
      NOP   0;
NETWORK
TITLE =AIR SUPPLY UNIT CONTROL LOOP B HUMIDIFYING ACTIVE

      U(    ;
      O     "COND_1_ASU_PR";
      O     ;
      U     "COND_4_ASU_PR";
      U(    ;
      L     "DB_GRP_81".CLM82_HUM.PV.AV;
      L     #H_81CLM82_HUM_SWP;
      <R    ;
      )     ;
      U(    ;
      L     "DB_GRP_81".VA41_M1.PV.Position;
      L     2.000000e+000;
      >R    ;
      )     ;
      )     ;
      S     "ASU_LOOP_B_ON";
      U     "COND_2_ASU_PR";
      R     "ASU_LOOP_B_ON";
      NOP   0;
NETWORK
TITLE =AIR SUPPLY UNIT CONTROL LOOP C HEATING ACTIVE

      U(    ;
      O(    ;
      U     "COND_2_ASU_PR";
      U(    ;
      L     "DB_GRP_81".CLT81.PV.AV;
      L     #T_81CLT81_HEAT_SWP;
      <R    ;
      )     ;
      U(    ;
      O(    ;
      L     "DB_GRP_81".VA41_M1.PV.Position;
      L     2.000000e+000;
      >R    ;
      )     ;
      O     "COMM_1";
      )     ;
      L     S5T#1S;
      SE    "T_ASU_LOOP_C_SET_DLY";
      NOP   0;
      NOP   0;
      NOP   0;
      U     "T_ASU_LOOP_C_SET_DLY";
      )     ;
      O     "COND_3_ASU_PR";
      )     ;
      S     "ASU_LOOP_C_ON";
      U     "COND_4_ASU_PR";
      R     "ASU_LOOP_C_ON";
      NOP   0;
NETWORK
TITLE =AIR RECIRCULATION UNIT ON
//********************************************************************************
//
//                           AIR RECIRCULATION UNIT
//
//********************************************************************************
//
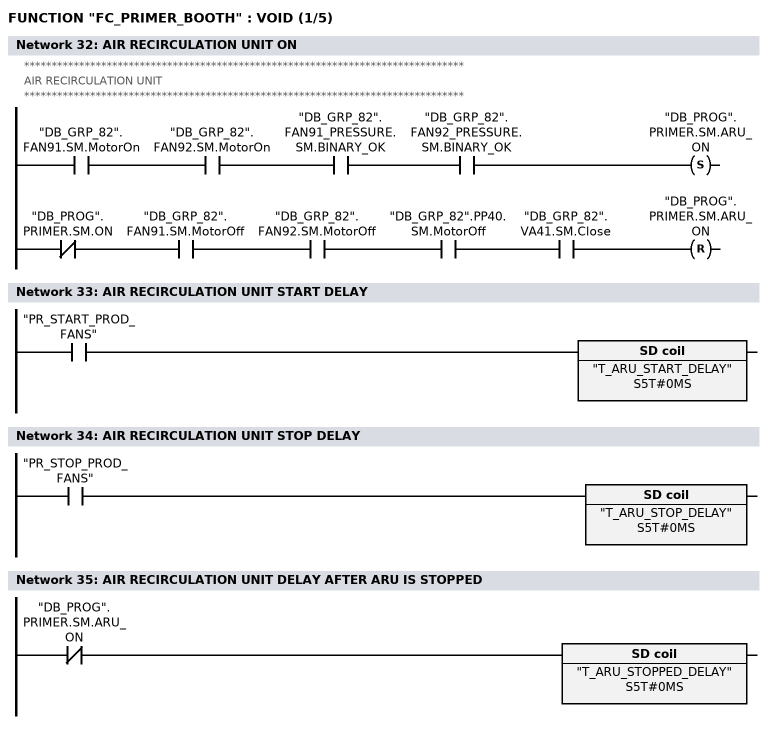
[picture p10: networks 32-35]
      U     "DB_GRP_82".FAN91.SM.MotorOn;
      U     "DB_GRP_82".FAN92.SM.MotorOn;
      U     "DB_GRP_82".FAN91_PRESSURE.SM.BINARY_OK;
      U     "DB_GRP_82".FAN92_PRESSURE.SM.BINARY_OK;
      S     "DB_PROG".PRIMER.SM.ARU_ON;
      UN    "DB_PROG".PRIMER.SM.ON;
      U     "DB_GRP_82".FAN91.SM.MotorOff;
      U     "DB_GRP_82".FAN92.SM.MotorOff;
      U     "DB_GRP_82".PP40.SM.MotorOff;
      U     "DB_GRP_82".VA41.SM.Close;
      R     "DB_PROG".PRIMER.SM.ARU_ON;
      NOP   0;
NETWORK
TITLE =AIR RECIRCULATION UNIT START DELAY

      U     "PR_START_PROD_FANS";
      L     S5T#0MS;
      SE    "T_ARU_START_DELAY";
      NOP   0;
      NOP   0;
      NOP   0;
      NOP   0;
NETWORK
TITLE =AIR RECIRCULATION UNIT STOP DELAY

      U     "PR_STOP_PROD_FANS";
      L     S5T#0MS;
      SE    "T_ARU_STOP_DELAY";
      NOP   0;
      NOP   0;
      NOP   0;
      NOP   0;
NETWORK
TITLE =AIR RECIRCULATION UNIT DELAY AFTER ARU IS STOPPED

      UN    "DB_PROG".PRIMER.SM.ARU_ON;
      L     S5T#0MS;
      SE    "T_ARU_STOPPED_DELAY";
      NOP   0;
      NOP   0;
      NOP   0;
      NOP   0;
NETWORK
TITLE =AIR RECIRUCULATION UNIT TEMP. AND HUMIDITY CONTROL ON

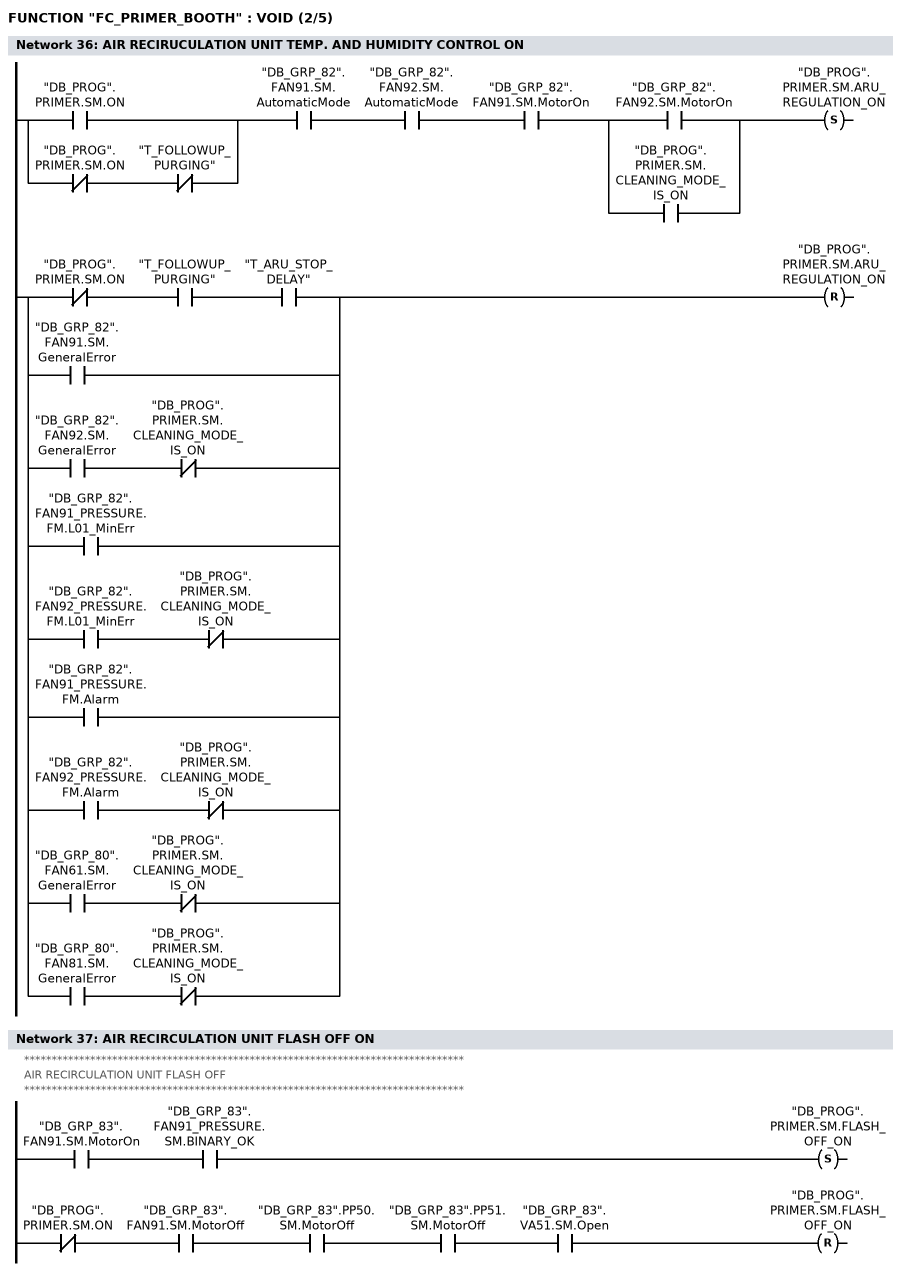
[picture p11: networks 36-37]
      U(    ;
      O     "DB_PROG".PRIMER.SM.ON;
      O     ;
      UN    "DB_PROG".PRIMER.SM.ON;
      UN    "T_FOLLOWUP_PURGING";
      )     ;
      U     "DB_GRP_82".FAN91.SM.AutomaticMode;
      U     "DB_GRP_82".FAN92.SM.AutomaticMode;
      U     "DB_GRP_82".FAN91.SM.MotorOn;
      U(    ;
      O     "DB_GRP_82".FAN92.SM.MotorOn;
      O     "DB_PROG".PRIMER.SM.CLEANING_MODE_IS_ON;
      )     ;
      S     "DB_PROG".PRIMER.SM.ARU_REGULATION_ON;
      U(    ;
      UN    "DB_PROG".PRIMER.SM.ON;
      U     "T_FOLLOWUP_PURGING";
      U     "T_ARU_STOP_DELAY";
      O     "DB_GRP_82".FAN91.SM.GeneralError;
      O     ;
      U     "DB_GRP_82".FAN92.SM.GeneralError;
      UN    "DB_PROG".PRIMER.SM.CLEANING_MODE_IS_ON;
      O     "DB_GRP_82".FAN91_PRESSURE.FM.L01_MinErr;
      O     ;
      U     "DB_GRP_82".FAN92_PRESSURE.FM.L01_MinErr;
      UN    "DB_PROG".PRIMER.SM.CLEANING_MODE_IS_ON;
      O     "DB_GRP_82".FAN91_PRESSURE.FM.Alarm;
      O     ;
      U     "DB_GRP_82".FAN92_PRESSURE.FM.Alarm;
      UN    "DB_PROG".PRIMER.SM.CLEANING_MODE_IS_ON;
      O     ;
      U     "DB_GRP_80".FAN61.SM.GeneralError;
      UN    "DB_PROG".PRIMER.SM.CLEANING_MODE_IS_ON;
      O     ;
      U     "DB_GRP_80".FAN81.SM.GeneralError;
      UN    "DB_PROG".PRIMER.SM.CLEANING_MODE_IS_ON;
      )     ;
      R     "DB_PROG".PRIMER.SM.ARU_REGULATION_ON;
      NOP   0;
NETWORK
TITLE =AIR RECIRCULATION UNIT FLASH OFF ON
//********************************************************************************
//
//                      AIR RECIRCULATION UNIT FLASH OFF
//
//********************************************************************************
//
      U     "DB_GRP_83".FAN91.SM.MotorOn;
      U     "DB_GRP_83".FAN91_PRESSURE.SM.BINARY_OK;
      S     "DB_PROG".PRIMER.SM.FLASH_OFF_ON;
      UN    "DB_PROG".PRIMER.SM.ON;
      U     "DB_GRP_83".FAN91.SM.MotorOff;
      U     "DB_GRP_83".PP50.SM.MotorOff;
      U     "DB_GRP_83".PP51.SM.MotorOff;
      U     "DB_GRP_83".VA51.SM.Open;
      R     "DB_PROG".PRIMER.SM.FLASH_OFF_ON;
      NOP   0;
NETWORK
TITLE =AIR RECIRCULATION UNIT FLASH OFF START DELAY

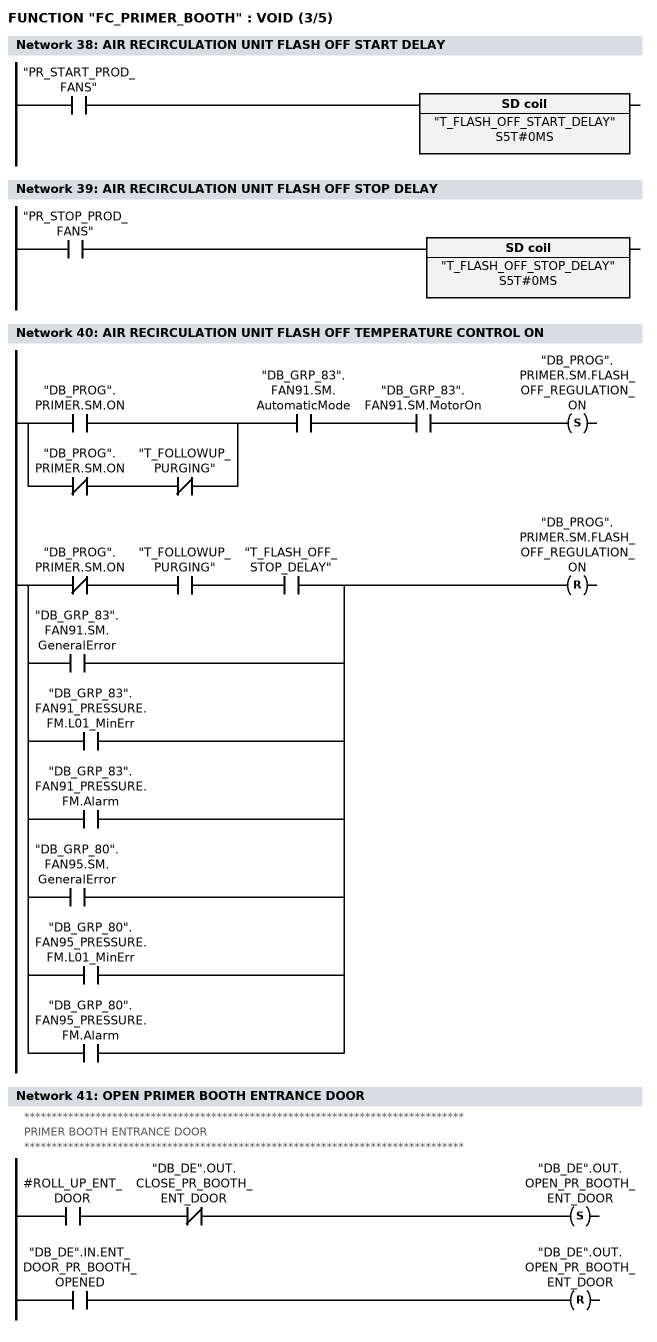
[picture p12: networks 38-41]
      U     "PR_START_PROD_FANS";
      L     S5T#0MS;
      SE    "T_FLASH_OFF_START_DELAY";
      NOP   0;
      NOP   0;
      NOP   0;
      NOP   0;
NETWORK
TITLE =AIR RECIRCULATION UNIT FLASH OFF STOP DELAY

      U     "PR_STOP_PROD_FANS";
      L     S5T#0MS;
      SE    "T_FLASH_OFF_STOP_DELAY";
      NOP   0;
      NOP   0;
      NOP   0;
      NOP   0;
NETWORK
TITLE =AIR RECIRCULATION UNIT FLASH OFF TEMPERATURE CONTROL ON

      U(    ;
      O     "DB_PROG".PRIMER.SM.ON;
      O     ;
      UN    "DB_PROG".PRIMER.SM.ON;
      UN    "T_FOLLOWUP_PURGING";
      )     ;
      U     "DB_GRP_83".FAN91.SM.AutomaticMode;
      U     "DB_GRP_83".FAN91.SM.MotorOn;
      S     "DB_PROG".PRIMER.SM.FLASH_OFF_REGULATION_ON;
      U(    ;
      UN    "DB_PROG".PRIMER.SM.ON;
      U     "T_FOLLOWUP_PURGING";
      U     "T_FLASH_OFF_STOP_DELAY";
      O     "DB_GRP_83".FAN91.SM.GeneralError;
      O     "DB_GRP_83".FAN91_PRESSURE.FM.L01_MinErr;
      O     "DB_GRP_83".FAN91_PRESSURE.FM.Alarm;
      O     "DB_GRP_80".FAN95.SM.GeneralError;
      O     "DB_GRP_80".FAN95_PRESSURE.FM.L01_MinErr;
      O     "DB_GRP_80".FAN95_PRESSURE.FM.Alarm;
      )     ;
      R     "DB_PROG".PRIMER.SM.FLASH_OFF_REGULATION_ON;
      NOP   0;
NETWORK
TITLE =OPEN PRIMER BOOTH ENTRANCE DOOR
//********************************************************************************
//
//                         PRIMER BOOTH ENTRANCE DOOR
//
//********************************************************************************
//
      U     #ROLL_UP_ENT_DOOR;
      UN    "DB_DE".OUT.CLOSE_PR_BOOTH_ENT_DOOR;
      S     "DB_DE".OUT.OPEN_PR_BOOTH_ENT_DOOR;
      U     "DB_DE".IN.ENT_DOOR_PR_BOOTH_OPENED;
      R     "DB_DE".OUT.OPEN_PR_BOOTH_ENT_DOOR;
      NOP   0;
NETWORK
TITLE =CLOSE PRIMER BOOTH ENTRANCE DOOR

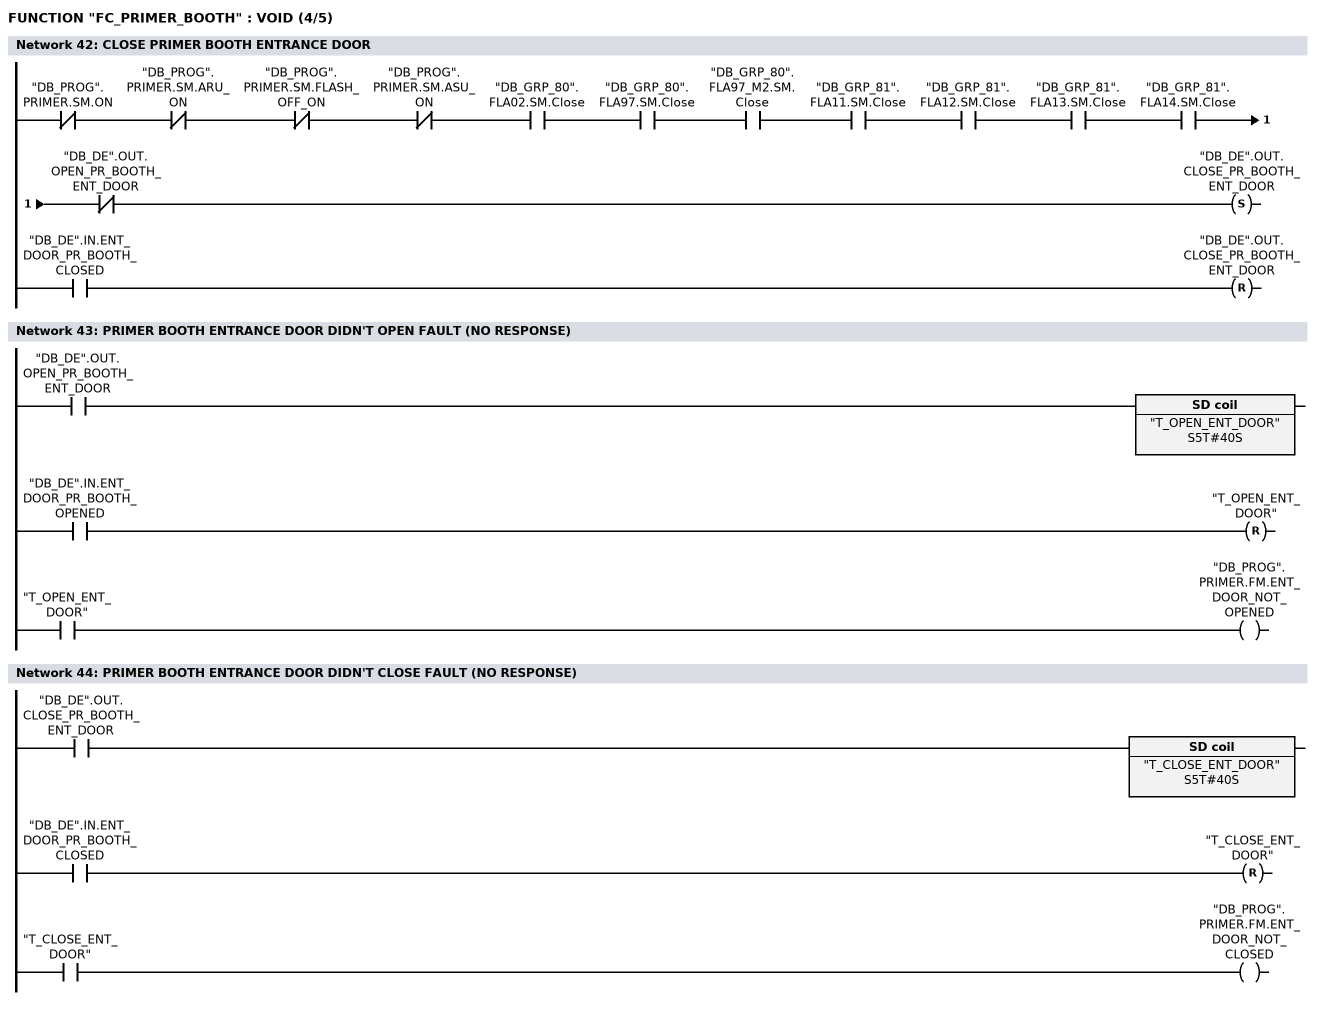
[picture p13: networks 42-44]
      UN    "DB_PROG".PRIMER.SM.ON;
      UN    "DB_PROG".PRIMER.SM.ARU_ON;
      UN    "DB_PROG".PRIMER.SM.FLASH_OFF_ON;
      UN    "DB_PROG".PRIMER.SM.ASU_ON;
      U     "DB_GRP_80".FLA02.SM.Close;
      U     "DB_GRP_80".FLA97.SM.Close;
      U     "DB_GRP_80".FLA97_M2.SM.Close;
      U     "DB_GRP_81".FLA11.SM.Close;
      U     "DB_GRP_81".FLA12.SM.Close;
      U     "DB_GRP_81".FLA13.SM.Close;
      U     "DB_GRP_81".FLA14.SM.Close;
      UN    "DB_DE".OUT.OPEN_PR_BOOTH_ENT_DOOR;
      S     "DB_DE".OUT.CLOSE_PR_BOOTH_ENT_DOOR;
      U     "DB_DE".IN.ENT_DOOR_PR_BOOTH_CLOSED;
      R     "DB_DE".OUT.CLOSE_PR_BOOTH_ENT_DOOR;
      NOP   0;
NETWORK
TITLE =PRIMER BOOTH ENTRANCE DOOR DIDN'T OPEN FAULT (NO RESPONSE)

      U     "DB_DE".OUT.OPEN_PR_BOOTH_ENT_DOOR;
      L     S5T#40S;
      SE    "T_OPEN_ENT_DOOR";
      U     "DB_DE".IN.ENT_DOOR_PR_BOOTH_OPENED;
      R     "T_OPEN_ENT_DOOR";
      NOP   0;
      NOP   0;
      U     "T_OPEN_ENT_DOOR";
      =     "DB_PROG".PRIMER.FM.ENT_DOOR_NOT_OPENED;
NETWORK
TITLE =PRIMER BOOTH ENTRANCE DOOR DIDN'T CLOSE FAULT (NO RESPONSE)

      U     "DB_DE".OUT.CLOSE_PR_BOOTH_ENT_DOOR;
      L     S5T#40S;
      SE    "T_CLOSE_ENT_DOOR";
      U     "DB_DE".IN.ENT_DOOR_PR_BOOTH_CLOSED;
      R     "T_CLOSE_ENT_DOOR";
      NOP   0;
      NOP   0;
      U     "T_CLOSE_ENT_DOOR";
      =     "DB_PROG".PRIMER.FM.ENT_DOOR_NOT_CLOSED;
NETWORK
TITLE =FOLLOW-UP PURGING TIMER SETPOINT
//********************************************************************************
//
//                                   PURGING
//
//********************************************************************************
//
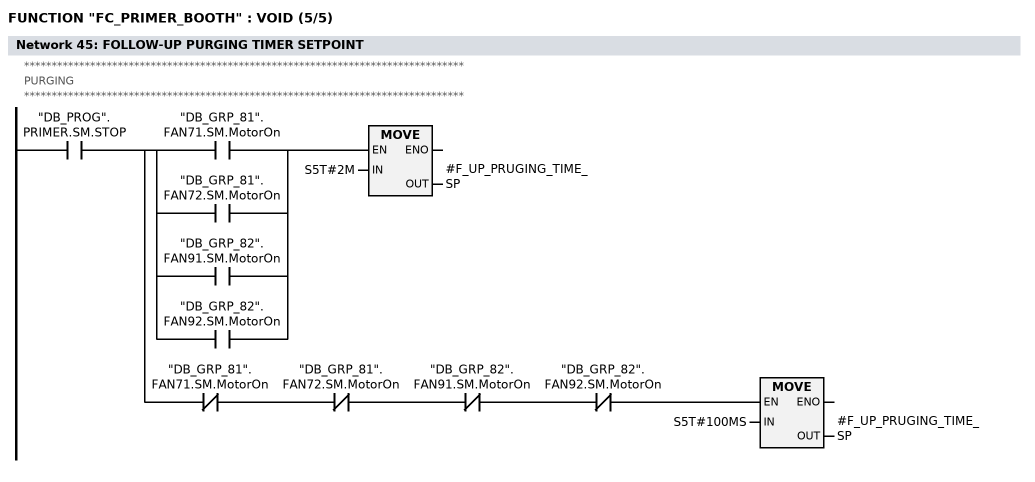
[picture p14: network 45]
      U     "DB_PROG".PRIMER.SM.STOP;
      =     L     26.0;
      U     L     26.0;
      U(    ;
      O     "DB_GRP_81".FAN71.SM.MotorOn;
      O     "DB_GRP_81".FAN72.SM.MotorOn;
      O     "DB_GRP_82".FAN91.SM.MotorOn;
      O     "DB_GRP_82".FAN92.SM.MotorOn;
      )     ;
      SPBNB _008;
      L     S5T#2M;
      T     #F_UP_PRUGING_TIME_SP;
_008: NOP   0;
      U     L     26.0;
      UN    "DB_GRP_81".FAN71.SM.MotorOn;
      UN    "DB_GRP_81".FAN72.SM.MotorOn;
      UN    "DB_GRP_82".FAN91.SM.MotorOn;
      UN    "DB_GRP_82".FAN92.SM.MotorOn;
      SPBNB _009;
      L     S5T#100MS;
      T     #F_UP_PRUGING_TIME_SP;
_009: NOP   0;
NETWORK
TITLE =FOLLOW UP PURGING TIMER - STOP VENTILATION

      U(    ;
      U     "DB_PROG".PRIMER.SM.STOP;
      UN    "DB_PROG".PRIMER.SM.PROD_RELEASE;
      =     #FOLLOW_UP_PURGING_ON;
      U     #FOLLOW_UP_PURGING_ON;
      L     #F_UP_PRUGING_TIME_SP;
      SE    "T_FOLLOWUP_PURGING";
      UN    "DB_PROG".PRIMER.SM.ASU_ON;
      UN    "DB_PROG".PRIMER.SM.ARU_ON;
      UN    "DB_PROG".PRIMER.SM.FLASH_OFF_ON;
      UN    "DB_PROG".PRIMER.SM.CLEANING_MODE_IS_ON;
      FP    "T_FOLLOW_UP_PURGING_PE";
      R     "T_FOLLOWUP_PURGING";
      NOP   0;
      NOP   0;
      U     "T_FOLLOWUP_PURGING";
      )     ;
      S     "PR_STOP_PROD_FANS";
      U     "DB_PROG".PRIMER.SM.ON;
      R     "PR_STOP_PROD_FANS";
      NOP   0;
NETWORK
TITLE =FOLLOW-UP PURGING TIMER RUNNING

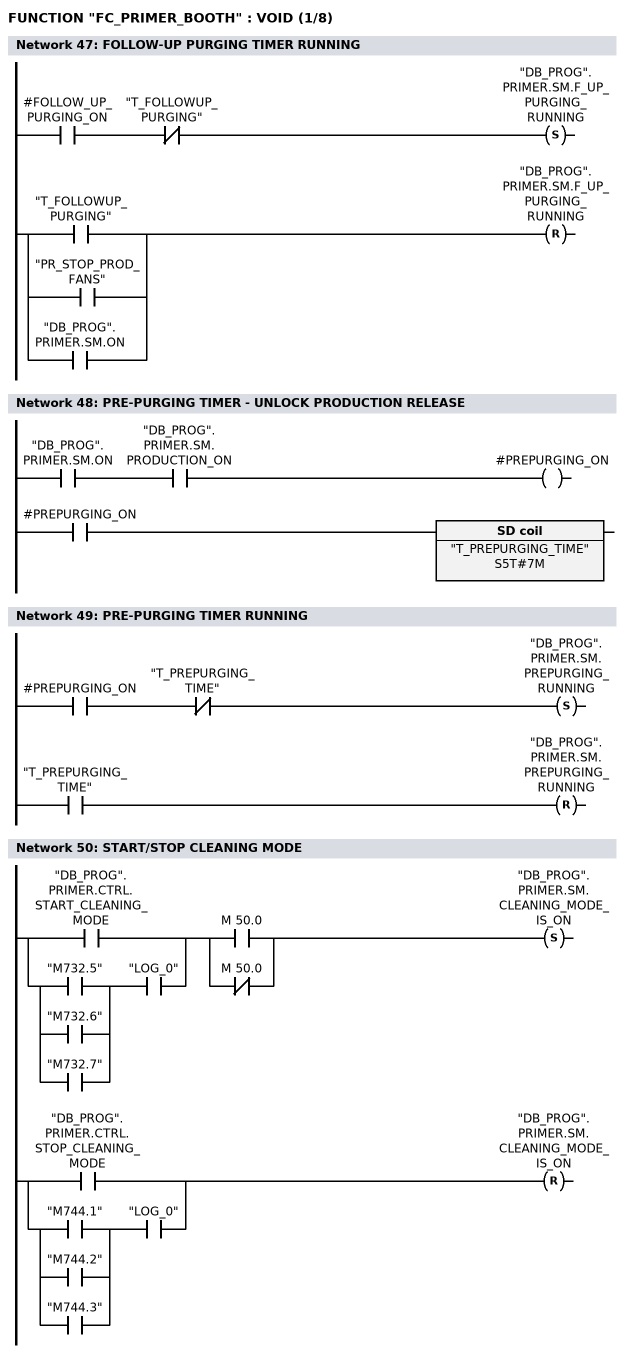
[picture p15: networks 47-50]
      U     #FOLLOW_UP_PURGING_ON;
      UN    "T_FOLLOWUP_PURGING";
      S     "DB_PROG".PRIMER.SM.F_UP_PURGING_RUNNING;
      U(    ;
      O     "T_FOLLOWUP_PURGING";
      O     "PR_STOP_PROD_FANS";
      O     "DB_PROG".PRIMER.SM.ON;
      )     ;
      R     "DB_PROG".PRIMER.SM.F_UP_PURGING_RUNNING;
      NOP   0;
NETWORK
TITLE =PRE-PURGING TIMER - UNLOCK PRODUCTION RELEASE

      U     "DB_PROG".PRIMER.SM.ON;
      U     "DB_PROG".PRIMER.SM.PRODUCTION_ON;
      =     #PREPURGING_ON;
      U     #PREPURGING_ON;
      L     S5T#7M;
      SE    "T_PREPURGING_TIME";
      NOP   0;
      NOP   0;
      NOP   0;
      NOP   0;
NETWORK
TITLE =PRE-PURGING TIMER RUNNING

      U     #PREPURGING_ON;
      UN    "T_PREPURGING_TIME";
      S     "DB_PROG".PRIMER.SM.PREPURGING_RUNNING;
      U     "T_PREPURGING_TIME";
      R     "DB_PROG".PRIMER.SM.PREPURGING_RUNNING;
      NOP   0;
NETWORK
TITLE =START/STOP CLEANING MODE

      U(    ;
      O     "DB_PROG".PRIMER.CTRL.START_CLEANING_MODE;
      O     ;
      U(    ;
      O     "M732.5";
      O     "M732.6";
      O     "M732.7";
      )     ;
      U     "LOG_0";
      )     ;
      U(    ;
      O     M     50.0;
      ON    M     50.0;
      )     ;
      S     "DB_PROG".PRIMER.SM.CLEANING_MODE_IS_ON;
      U(    ;
      O     "DB_PROG".PRIMER.CTRL.STOP_CLEANING_MODE;
      O     ;
      U(    ;
      O     "M744.1";
      O     "M744.2";
      O     "M744.3";
      )     ;
      U     "LOG_0";
      )     ;
      R     "DB_PROG".PRIMER.SM.CLEANING_MODE_IS_ON;
      NOP   0;
NETWORK
TITLE =START/STOP SOLVENTE MODE

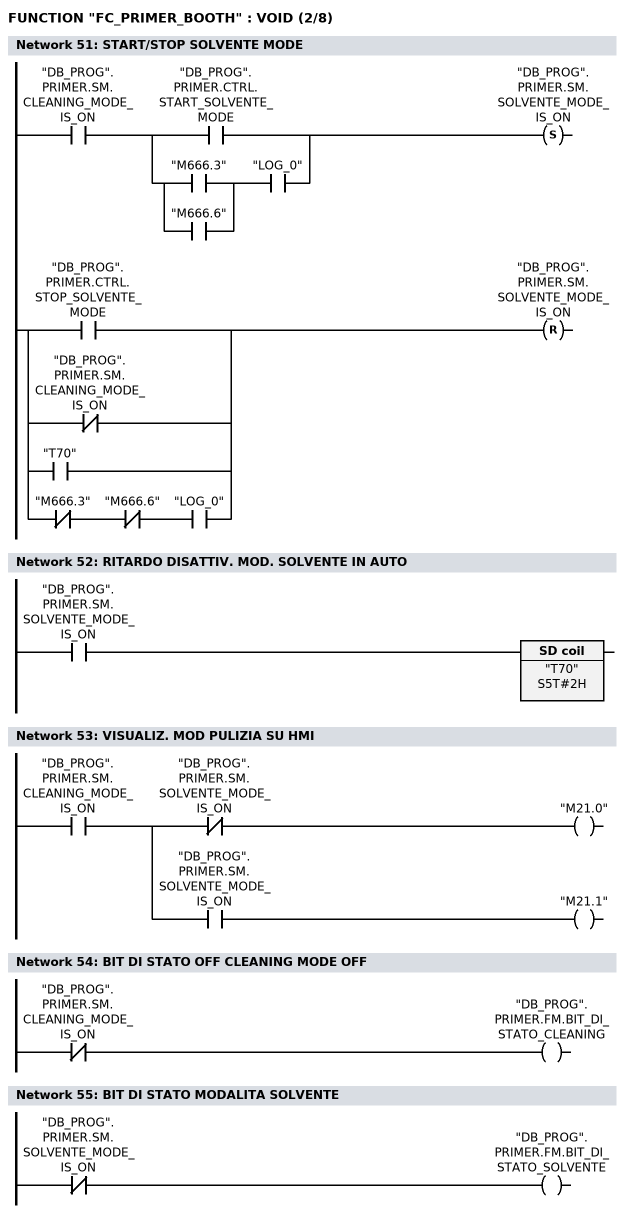
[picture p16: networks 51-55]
      U     "DB_PROG".PRIMER.SM.CLEANING_MODE_IS_ON;
      U(    ;
      O     "DB_PROG".PRIMER.CTRL.START_SOLVENTE_MODE;
      O     ;
      U(    ;
      O     "M666.3";
      O     "M666.6";
      )     ;
      U     "LOG_0";
      )     ;
      S     "DB_PROG".PRIMER.SM.SOLVENTE_MODE_IS_ON;
      U(    ;
      O     "DB_PROG".PRIMER.CTRL.STOP_SOLVENTE_MODE;
      ON    "DB_PROG".PRIMER.SM.CLEANING_MODE_IS_ON;
      O     "T70";
      O     ;
      UN    "M666.3";
      UN    "M666.6";
      U     "LOG_0";
      )     ;
      R     "DB_PROG".PRIMER.SM.SOLVENTE_MODE_IS_ON;
      NOP   0;
NETWORK
TITLE =RITARDO DISATTIV. MOD. SOLVENTE IN AUTO

      U     "DB_PROG".PRIMER.SM.SOLVENTE_MODE_IS_ON;
      L     S5T#2H;
      SE    "T70";
      NOP   0;
      NOP   0;
      NOP   0;
      NOP   0;
NETWORK
TITLE =VISUALIZ. MOD PULIZIA SU HMI

      U     "DB_PROG".PRIMER.SM.CLEANING_MODE_IS_ON;
      =     L     26.0;
      U     L     26.0;
      UN    "DB_PROG".PRIMER.SM.SOLVENTE_MODE_IS_ON;
      =     "M21.0";
      U     L     26.0;
      U     "DB_PROG".PRIMER.SM.SOLVENTE_MODE_IS_ON;
      =     "M21.1";
NETWORK
TITLE =BIT DI STATO OFF CLEANING MODE OFF

      UN    "DB_PROG".PRIMER.SM.CLEANING_MODE_IS_ON;
      =     "DB_PROG".PRIMER.FM.BIT_DI_STATO_CLEANING;
NETWORK
TITLE =BIT DI STATO MODALITA SOLVENTE

      UN    "DB_PROG".PRIMER.SM.SOLVENTE_MODE_IS_ON;
      =     "DB_PROG".PRIMER.FM.BIT_DI_STATO_SOLVENTE;
NETWORK
TITLE =PUMP SUMPS ON
//********************************************************************************
//
//                                 PUMP SUMPS
//
//********************************************************************************
//
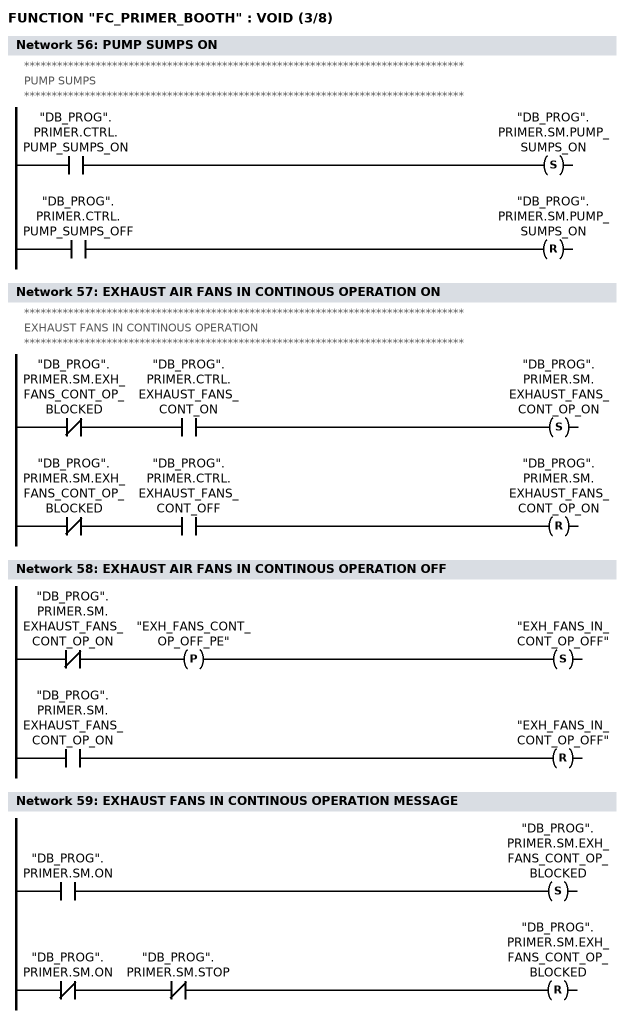
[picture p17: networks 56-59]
      U     "DB_PROG".PRIMER.CTRL.PUMP_SUMPS_ON;
      S     "DB_PROG".PRIMER.SM.PUMP_SUMPS_ON;
      U     "DB_PROG".PRIMER.CTRL.PUMP_SUMPS_OFF;
      R     "DB_PROG".PRIMER.SM.PUMP_SUMPS_ON;
      NOP   0;
NETWORK
TITLE =EXHAUST AIR FANS IN CONTINOUS OPERATION ON
//********************************************************************************
//
//                    EXHAUST FANS IN CONTINOUS OPERATION
//
//********************************************************************************
//
      UN    "DB_PROG".PRIMER.SM.EXH_FANS_CONT_OP_BLOCKED;
      U     "DB_PROG".PRIMER.CTRL.EXHAUST_FANS_CONT_ON;
      S     "DB_PROG".PRIMER.SM.EXHAUST_FANS_CONT_OP_ON;
      UN    "DB_PROG".PRIMER.SM.EXH_FANS_CONT_OP_BLOCKED;
      U     "DB_PROG".PRIMER.CTRL.EXHAUST_FANS_CONT_OFF;
      R     "DB_PROG".PRIMER.SM.EXHAUST_FANS_CONT_OP_ON;
      NOP   0;
NETWORK
TITLE =EXHAUST AIR FANS IN CONTINOUS OPERATION OFF

      UN    "DB_PROG".PRIMER.SM.EXHAUST_FANS_CONT_OP_ON;
      FP    "EXH_FANS_CONT_OP_OFF_PE";
      S     "EXH_FANS_IN_CONT_OP_OFF";
      U     "DB_PROG".PRIMER.SM.EXHAUST_FANS_CONT_OP_ON;
      R     "EXH_FANS_IN_CONT_OP_OFF";
      NOP   0;
NETWORK
TITLE =EXHAUST FANS IN CONTINOUS OPERATION MESSAGE

      U     "DB_PROG".PRIMER.SM.ON;
      S     "DB_PROG".PRIMER.SM.EXH_FANS_CONT_OP_BLOCKED;
      UN    "DB_PROG".PRIMER.SM.ON;
      UN    "DB_PROG".PRIMER.SM.STOP;
      R     "DB_PROG".PRIMER.SM.EXH_FANS_CONT_OP_BLOCKED;
      NOP   0;
NETWORK
TITLE =PROCESS CONDITIONS
//********************************************************************************
//
//                              PROCESS CONDITIONS
//
//********************************************************************************
//
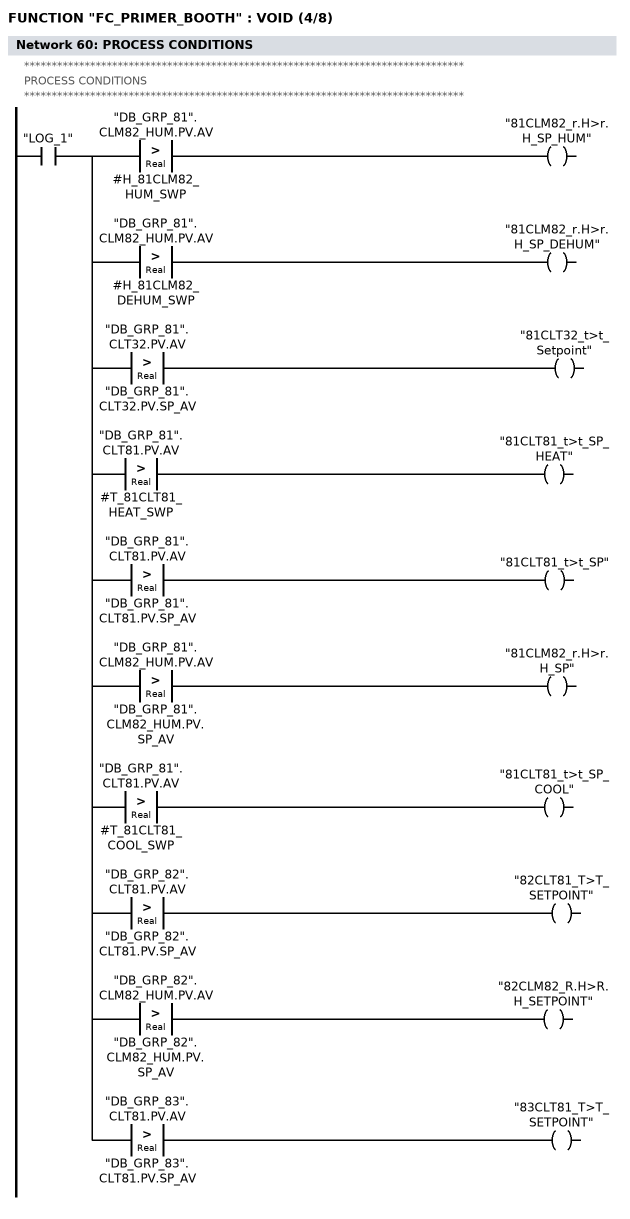
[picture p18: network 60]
      U     "LOG_1";
      =     L     26.0;
      U     L     26.0;
      U(    ;
      L     "DB_GRP_81".CLM82_HUM.PV.AV;
      L     #H_81CLM82_HUM_SWP;
      >R    ;
      )     ;
      =     "81CLM82_r.H>r.H_SP_HUM";
      U     L     26.0;
      U(    ;
      L     "DB_GRP_81".CLM82_HUM.PV.AV;
      L     #H_81CLM82_DEHUM_SWP;
      >R    ;
      )     ;
      =     "81CLM82_r.H>r.H_SP_DEHUM";
      U     L     26.0;
      U(    ;
      L     "DB_GRP_81".CLT32.PV.AV;
      L     "DB_GRP_81".CLT32.PV.SP_AV;
      >R    ;
      )     ;
      =     "81CLT32_t>t_Setpoint";
      U     L     26.0;
      U(    ;
      L     "DB_GRP_81".CLT81.PV.AV;
      L     #T_81CLT81_HEAT_SWP;
      >R    ;
      )     ;
      =     "81CLT81_t>t_SP_HEAT";
      U     L     26.0;
      U(    ;
      L     "DB_GRP_81".CLT81.PV.AV;
      L     "DB_GRP_81".CLT81.PV.SP_AV;
      >R    ;
      )     ;
      =     "81CLT81_t>t_SP";
      U     L     26.0;
      U(    ;
      L     "DB_GRP_81".CLM82_HUM.PV.AV;
      L     "DB_GRP_81".CLM82_HUM.PV.SP_AV;
      >R    ;
      )     ;
      =     "81CLM82_r.H>r.H_SP";
      U     L     26.0;
      U(    ;
      L     "DB_GRP_81".CLT81.PV.AV;
      L     #T_81CLT81_COOL_SWP;
      >R    ;
      )     ;
      =     "81CLT81_t>t_SP_COOL";
      U     L     26.0;
      U(    ;
      L     "DB_GRP_82".CLT81.PV.AV;
      L     "DB_GRP_82".CLT81.PV.SP_AV;
      >R    ;
      )     ;
      =     "82CLT81_T>T_SETPOINT";
      U     L     26.0;
      U(    ;
      L     "DB_GRP_82".CLM82_HUM.PV.AV;
      L     "DB_GRP_82".CLM82_HUM.PV.SP_AV;
      >R    ;
      )     ;
      =     "82CLM82_R.H>R.H_SETPOINT";
      U     L     26.0;
      U(    ;
      L     "DB_GRP_83".CLT81.PV.AV;
      L     "DB_GRP_83".CLT81.PV.SP_AV;
      >R    ;
      )     ;
      =     "83CLT81_T>T_SETPOINT";
NETWORK
TITLE =PRIMER BOOTH TEMPERATURE IN RANGE
//********************************************************************************
//
//                         PRIMER BOOTH PRODUCTION RELEASE
//
//********************************************************************************
//
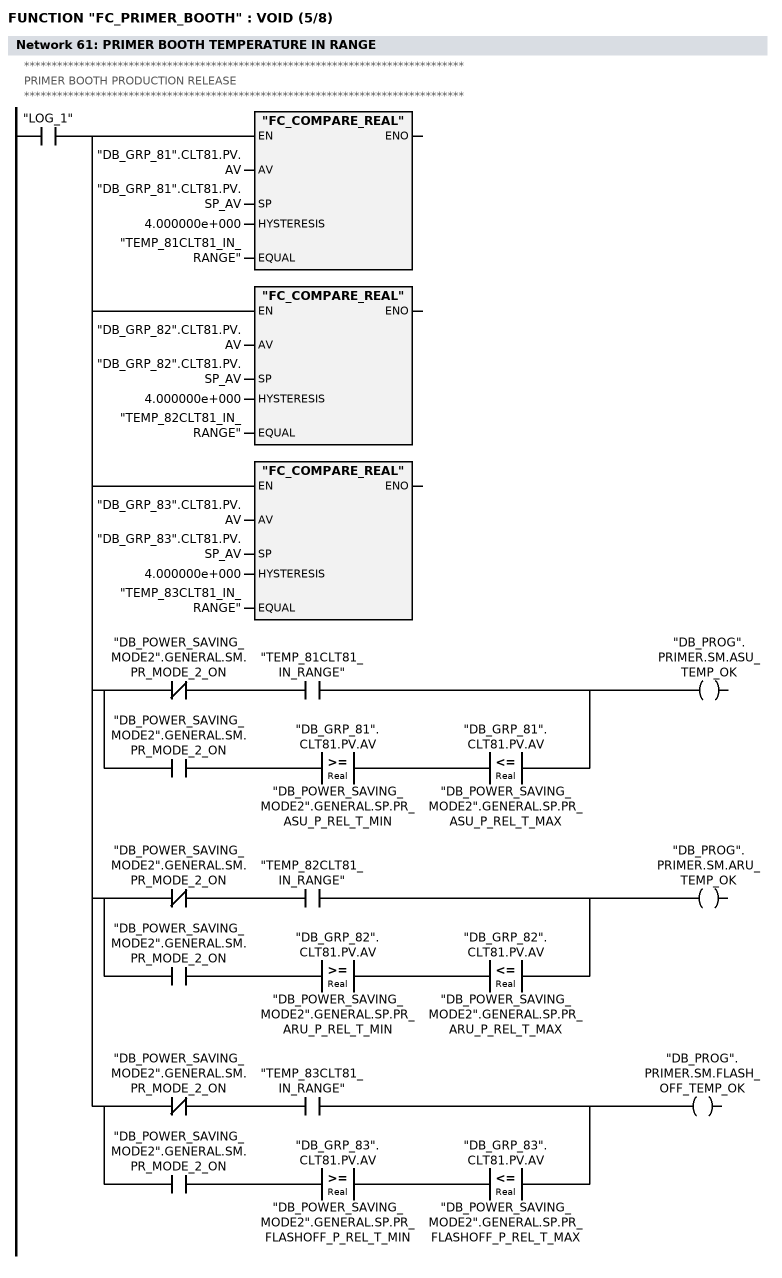
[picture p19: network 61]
      U     "LOG_1";
      =     L     26.0;
      U     L     26.0;
      SPBNB _00a;
      CALL "FC_COMPARE_REAL" (
           AV                       := "DB_GRP_81".CLT81.PV.AV,
           SP                       := "DB_GRP_81".CLT81.PV.SP_AV,
           HYSTERESIS               := 4.000000e+000,
           EQUAL                    := "TEMP_81CLT81_IN_RANGE");
_00a: NOP   0;
      U     L     26.0;
      SPBNB _00b;
      CALL "FC_COMPARE_REAL" (
           AV                       := "DB_GRP_82".CLT81.PV.AV,
           SP                       := "DB_GRP_82".CLT81.PV.SP_AV,
           HYSTERESIS               := 4.000000e+000,
           EQUAL                    := "TEMP_82CLT81_IN_RANGE");
_00b: NOP   0;
      U     L     26.0;
      SPBNB _00c;
      CALL "FC_COMPARE_REAL" (
           AV                       := "DB_GRP_83".CLT81.PV.AV,
           SP                       := "DB_GRP_83".CLT81.PV.SP_AV,
           HYSTERESIS               := 4.000000e+000,
           EQUAL                    := "TEMP_83CLT81_IN_RANGE");
_00c: NOP   0;
      U     L     26.0;
      U(    ;
      UN    "DB_POWER_SAVING_MODE2".GENERAL.SM.PR_MODE_2_ON;
      U     "TEMP_81CLT81_IN_RANGE";
      O     ;
      U     "DB_POWER_SAVING_MODE2".GENERAL.SM.PR_MODE_2_ON;
      U(    ;
      L     "DB_GRP_81".CLT81.PV.AV;
      L     "DB_POWER_SAVING_MODE2".GENERAL.SP.PR_ASU_P_REL_T_MIN;
      >=R   ;
      )     ;
      U(    ;
      L     "DB_GRP_81".CLT81.PV.AV;
      L     "DB_POWER_SAVING_MODE2".GENERAL.SP.PR_ASU_P_REL_T_MAX;
      <=R   ;
      )     ;
      )     ;
      =     "DB_PROG".PRIMER.SM.ASU_TEMP_OK;
      U     L     26.0;
      U(    ;
      UN    "DB_POWER_SAVING_MODE2".GENERAL.SM.PR_MODE_2_ON;
      U     "TEMP_82CLT81_IN_RANGE";
      O     ;
      U     "DB_POWER_SAVING_MODE2".GENERAL.SM.PR_MODE_2_ON;
      U(    ;
      L     "DB_GRP_82".CLT81.PV.AV;
      L     "DB_POWER_SAVING_MODE2".GENERAL.SP.PR_ARU_P_REL_T_MIN;
      >=R   ;
      )     ;
      U(    ;
      L     "DB_GRP_82".CLT81.PV.AV;
      L     "DB_POWER_SAVING_MODE2".GENERAL.SP.PR_ARU_P_REL_T_MAX;
      <=R   ;
      )     ;
      )     ;
      =     "DB_PROG".PRIMER.SM.ARU_TEMP_OK;
      U     L     26.0;
      U(    ;
      UN    "DB_POWER_SAVING_MODE2".GENERAL.SM.PR_MODE_2_ON;
      U     "TEMP_83CLT81_IN_RANGE";
      O     ;
      U     "DB_POWER_SAVING_MODE2".GENERAL.SM.PR_MODE_2_ON;
      U(    ;
      L     "DB_GRP_83".CLT81.PV.AV;
      L     "DB_POWER_SAVING_MODE2".GENERAL.SP.PR_FLASHOFF_P_REL_T_MIN;
      >=R   ;
      )     ;
      U(    ;
      L     "DB_GRP_83".CLT81.PV.AV;
      L     "DB_POWER_SAVING_MODE2".GENERAL.SP.PR_FLASHOFF_P_REL_T_MAX;
      <=R   ;
      )     ;
      )     ;
      =     "DB_PROG".PRIMER.SM.FLASH_OFF_TEMP_OK;
NETWORK
TITLE =PRIMER BOOTH HUMIDITY IN RANGE

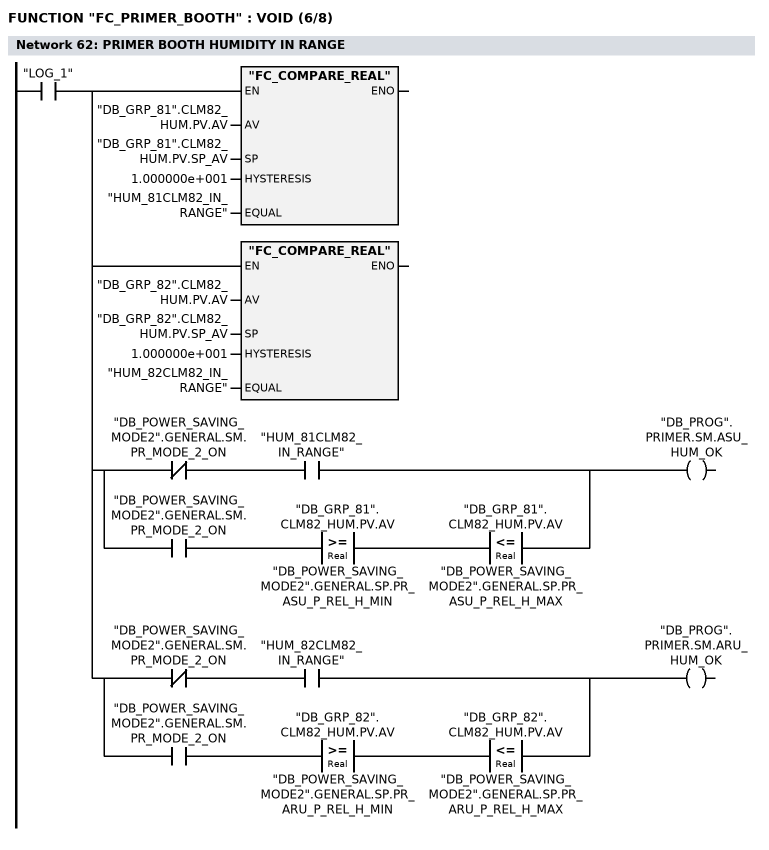
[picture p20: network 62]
      U     "LOG_1";
      =     L     26.0;
      U     L     26.0;
      SPBNB _00d;
      CALL "FC_COMPARE_REAL" (
           AV                       := "DB_GRP_81".CLM82_HUM.PV.AV,
           SP                       := "DB_GRP_81".CLM82_HUM.PV.SP_AV,
           HYSTERESIS               := 1.000000e+001,
           EQUAL                    := "HUM_81CLM82_IN_RANGE");
_00d: NOP   0;
      U     L     26.0;
      SPBNB _00e;
      CALL "FC_COMPARE_REAL" (
           AV                       := "DB_GRP_82".CLM82_HUM.PV.AV,
           SP                       := "DB_GRP_82".CLM82_HUM.PV.SP_AV,
           HYSTERESIS               := 1.000000e+001,
           EQUAL                    := "HUM_82CLM82_IN_RANGE");
_00e: NOP   0;
      U     L     26.0;
      U(    ;
      UN    "DB_POWER_SAVING_MODE2".GENERAL.SM.PR_MODE_2_ON;
      U     "HUM_81CLM82_IN_RANGE";
      O     ;
      U     "DB_POWER_SAVING_MODE2".GENERAL.SM.PR_MODE_2_ON;
      U(    ;
      L     "DB_GRP_81".CLM82_HUM.PV.AV;
      L     "DB_POWER_SAVING_MODE2".GENERAL.SP.PR_ASU_P_REL_H_MIN;
      >=R   ;
      )     ;
      U(    ;
      L     "DB_GRP_81".CLM82_HUM.PV.AV;
      L     "DB_POWER_SAVING_MODE2".GENERAL.SP.PR_ASU_P_REL_H_MAX;
      <=R   ;
      )     ;
      )     ;
      =     "DB_PROG".PRIMER.SM.ASU_HUM_OK;
      U     L     26.0;
      U(    ;
      UN    "DB_POWER_SAVING_MODE2".GENERAL.SM.PR_MODE_2_ON;
      U     "HUM_82CLM82_IN_RANGE";
      O     ;
      U     "DB_POWER_SAVING_MODE2".GENERAL.SM.PR_MODE_2_ON;
      U(    ;
      L     "DB_GRP_82".CLM82_HUM.PV.AV;
      L     "DB_POWER_SAVING_MODE2".GENERAL.SP.PR_ARU_P_REL_H_MIN;
      >=R   ;
      )     ;
      U(    ;
      L     "DB_GRP_82".CLM82_HUM.PV.AV;
      L     "DB_POWER_SAVING_MODE2".GENERAL.SP.PR_ARU_P_REL_H_MAX;
      <=R   ;
      )     ;
      )     ;
      =     "DB_PROG".PRIMER.SM.ARU_HUM_OK;
NETWORK
TITLE =PRIMER BOOTH FILTER PRESSSURE IN RANGE

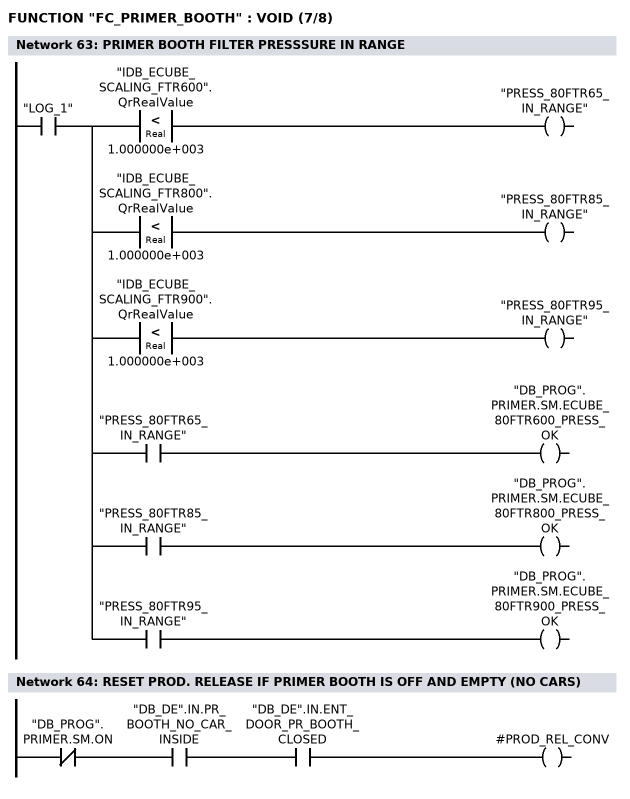
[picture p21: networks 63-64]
      U     "LOG_1";
      =     L     26.0;
      U     L     26.0;
      U(    ;
      L     "IDB_ECUBE_SCALING_FTR600".QrRealValue;
      L     1.000000e+003;
      <R    ;
      )     ;
      =     "PRESS_80FTR65_IN_RANGE";
      U     L     26.0;
      U(    ;
      L     "IDB_ECUBE_SCALING_FTR800".QrRealValue;
      L     1.000000e+003;
      <R    ;
      )     ;
      =     "PRESS_80FTR85_IN_RANGE";
      U     L     26.0;
      U(    ;
      L     "IDB_ECUBE_SCALING_FTR900".QrRealValue;
      L     1.000000e+003;
      <R    ;
      )     ;
      =     "PRESS_80FTR95_IN_RANGE";
      U     L     26.0;
      U     "PRESS_80FTR65_IN_RANGE";
      =     "DB_PROG".PRIMER.SM.ECUBE_80FTR600_PRESS_OK;
      U     L     26.0;
      U     "PRESS_80FTR85_IN_RANGE";
      =     "DB_PROG".PRIMER.SM.ECUBE_80FTR800_PRESS_OK;
      U     L     26.0;
      U     "PRESS_80FTR95_IN_RANGE";
      =     "DB_PROG".PRIMER.SM.ECUBE_80FTR900_PRESS_OK;
NETWORK
TITLE =RESET PROD. RELEASE IF PRIMER BOOTH IS OFF AND EMPTY (NO CARS)

      UN    "DB_PROG".PRIMER.SM.ON;
      U     "DB_DE".IN.PR_BOOTH_NO_CAR_INSIDE;
      U     "DB_DE".IN.ENT_DOOR_PR_BOOTH_CLOSED;
      =     #PROD_REL_CONV;
NETWORK
TITLE =RESET PROD. RELEASE IN CASE OF FAULTS
//UNBLOCK E-CUBE CHANGE DEMAND FAULTS IF PROBLEM WITH FILLING LEVEL CALCULATIONS
//IS FIXED - "LOG_0"
      O     "DB_GRP_82".FAN91.SM.GeneralError;
      O     "DB_GRP_82".FAN92.SM.GeneralError;
      O     "DB_GRP_82".FAN91_PRESSURE.FM.L01_MinErr;
      O     "DB_GRP_82".FAN92_PRESSURE.FM.L01_MinErr;
      O     "DB_GRP_82".FAN91_PRESSURE.FM.Alarm;
      O     "DB_GRP_82".FAN92_PRESSURE.FM.Alarm;
      O     "DB_GRP_82".CLM82_HUM.FM.L01_MinErr;
      O     "DB_GRP_82".CLM82_HUM.FM.L04_MaxErr;
      O     "DB_GRP_82".CLT81.FM.L01_MinErr;
      O     "DB_GRP_82".CLT81.FM.L04_MaxErr;
      O     "DB_GRP_83".FAN91.SM.GeneralError;
      O     "DB_GRP_83".FAN91_PRESSURE.FM.L01_MinErr;
      O     "DB_GRP_83".FAN91_PRESSURE.FM.Alarm;
      O     "DB_GRP_83".CLT81.FM.L01_MinErr;
      O     "DB_GRP_83".CLT81.FM.L04_MaxErr;
      O     "DB_GRP_81".FAN71.SM.GeneralError;
      O     "DB_GRP_81".FAN72.SM.GeneralError;
      O     "DB_DIGIT".FM.G81_FAN71;
      O     "DB_DIGIT".FM.G81_FAN72;
      ON    "FDB_DIGIT".R27_81DOO08_OK;
      O     "DB_GRP_81".CLM82_HUM.FM.L01_MinErr;
      O     "DB_GRP_81".CLM82_HUM.FM.L04_MaxErr;
      O     "DB_GRP_81".CLT81.FM.L01_MinErr;
      O     "DB_GRP_81".CLT81.FM.L04_MaxErr;
      O     "DB_DIGIT".FM.G81_MT34_A41_L2;
      O     "DB_DIGIT".FM.G81_MT34_1_L2;
      O     "DB_GRP_80".FAN01.SM.GeneralError;
      O     "DB_GRP_80".FAN58.SM.GeneralError;
      O     "DB_GRP_80".FAN61.SM.GeneralError;
      O     "DB_GRP_80".FAN62.SM.GeneralError;
      O     "DB_GRP_80".FAN91.SM.GeneralError;
      O     "DB_DIGIT".FM.G80_FAN01;
      O     "DB_GRP_80".FAN81.SM.GeneralError;
      O     "DB_GRP_80".FAN95.SM.GeneralError;
      O     "DB_GRP_80".FAN95_PRESSURE.FM.L01_MinErr;
      O     "DB_GRP_80".FAN95_PRESSURE.FM.Alarm;
      O     ;
      U     "DB_GRP_80".FAN92.SM.GeneralError;
      U     "DB_GRP_80".FAN93.SM.GeneralError;
      O     ;
      U(    ;
      O     "DB_GRP_80".FAN92_PRESSURE.FM.L01_MinErr;
      O     "DB_GRP_80".FAN92_PRESSURE.FM.Alarm;
      )     ;
      U(    ;
      O     "DB_GRP_80".FAN93_PRESSURE.FM.L01_MinErr;
      O     "DB_GRP_80".FAN93_PRESSURE.FM.Alarm;
      )     ;
      O     "DB_DIGIT".FM.G82_MO21_B511_ALARM;
      O     "DB_DIGIT".FM.G82_MO21_B512_ALARM;
      O     "DB_DIGIT".FM.G83_MO21_B511_ALARM;
      O     "DB_DIGIT".FM.G83_MO21_B512_ALARM;
      O     "DB_GRP_82".MO21_B51_1.FM.L04_MaxErr;
      O     "DB_GRP_82".MO21_B51_2.FM.L04_MaxErr;
      O     "DB_GRP_83".MO21_B51_1.FM.L04_MaxErr;
      O     "DB_GRP_83".MO21_B51_2.FM.L04_MaxErr;
      O     ;
      U     "DB_ECUBE_80FTR600_DE".OUT.FM.Change_demand;
      U     "LOG_0";
      O     ;
      U     "DB_ECUBE_80FTR800_DE".OUT.FM.Change_demand;
      U     "LOG_0";
      O     ;
      U     "DB_ECUBE_80FTR900_DE".OUT.FM.Change_demand;
      U     "LOG_0";
      =     #PROD_REL_FAULT;
NETWORK
TITLE =PRIMER BOOTH PRODUCTION RELEASE

      U(    ;
      U     "DB_PROG".PRIMER.SM.ON;
      U     "DB_PROG".PRIMER.SM.PRODUCTION_ON;
      U     "T_PREPURGING_TIME";
      U     "DB_PROG".PRIMER.SM.ASU_TEMP_OK;
      U     "DB_PROG".PRIMER.SM.ARU_TEMP_OK;
      U     "DB_PROG".PRIMER.SM.FLASH_OFF_TEMP_OK;
      U     "DB_PROG".PRIMER.SM.ASU_HUM_OK;
      U     "DB_PROG".PRIMER.SM.ARU_HUM_OK;
      U     "PRESS_80FTR65_IN_RANGE";
      U     "PRESS_80FTR85_IN_RANGE";
      U     "PRESS_80FTR95_IN_RANGE";
      L     S5T#10S;
      SE    "T_PROD_RELEASE";
      NOP   0;
      NOP   0;
      NOP   0;
      U     "T_PROD_RELEASE";
      )     ;
      UN    #PROD_REL_FAULT;
      UN    #PROD_REL_CONV;
      S     "DB_PROG".PRIMER.SM.PROD_RELEASE;
      U(    ;
      ON    "DB_PROG".PRIMER.SM.ON;
      O     #PROD_REL_FAULT;
      O     #PROD_REL_CONV;
      O(    ;
      U(    ;
      ON    "DB_PROG".PRIMER.SM.ASU_TEMP_OK;
      ON    "DB_PROG".PRIMER.SM.ARU_TEMP_OK;
      ON    "DB_PROG".PRIMER.SM.FLASH_OFF_TEMP_OK;
      ON    "DB_PROG".PRIMER.SM.ASU_HUM_OK;
      ON    "DB_PROG".PRIMER.SM.ARU_HUM_OK;
      ON    "PRESS_80FTR65_IN_RANGE";
      ON    "PRESS_80FTR85_IN_RANGE";
      ON    "PRESS_80FTR95_IN_RANGE";
      )     ;
      L     S5T#10S;
      SE    "T_PROD_RELEASE_LOST_DEL";
      NOP   0;
      NOP   0;
      NOP   0;
      U     "T_PROD_RELEASE_LOST_DEL";
      )     ;
      )     ;
      R     "DB_PROG".PRIMER.SM.PROD_RELEASE;
      NOP   0;
NETWORK
TITLE =PRIMER BOOTH FORCE PRODUCTION RELEASE

      U     "DB_PROG".PRIMER.CTRL.PR_BRIDGE_PROD_RELEASE;
      S     "DB_PROG".PRIMER.SM.PROD_RELEASE_BRIDGED;
      U     "DB_PROG".PRIMER.CTRL.PR_UNBRIDGE_PROD_RELEASE;
      R     "DB_PROG".PRIMER.SM.PROD_RELEASE_BRIDGED;
      U     "DB_PROG".PRIMER.SM.PROD_RELEASE_BRIDGED;
      =     "DB_DE".OUT.RELEASE_PR_BOOTH_BRIDGED;
NETWORK
TITLE =PRIMER BOOTH RELEASE FOR CONVEYORS
//ADDED SAFETY RELEASE FOR CONVEYING INTO PRIMER BOOTH (DB910.DBX34.2)
//
//27042016 - VT
      U(    ;
      U     "DB_PROG".PRIMER.SM.PROD_RELEASE;
      U     "DB_PROG".PRIMER.SM.ON;
      O     "DB_PROG".PRIMER.SM.PROD_RELEASE_BRIDGED;
      )     ;
      U     "FDB_DIGIT".RELEASE_CONV_BOOTH;
      =     "DB_DE".OUT.RELEASE_PR_BOOTH;
NETWORK
TITLE =GENERAL FAULTS
//********************************************************************************
//
//                                   GENERAL FAULTS
//
//********************************************************************************
//
//
//UNBLOCK E-CUBE CHANGE DEMAND AND FILLING LEVEL FAULTS IF PROBLEM WITH FILLING
//LEVEL CALCULATIONS IS FIXED
// GROUP 61
      U     "DB_GRP_61".CLV02_B40N_1.SM.GeneralError;
      O     "DB_GRP_61".CLV02_B40N_2.SM.GeneralError;
      O     "DB_GRP_61".CLV02_B25.SM.GeneralError;
      =     "GENERAL_FAULT_GROUP_61";

// GROUP 62
      U     "DB_GRP_62".CLV01_B40N_1.SM.GeneralError;
      O     "DB_GRP_62".CLV01_B40N_2.SM.GeneralError;
      O     "DB_GRP_62".CLV01_B25.SM.GeneralError;
      O     "DB_GRP_62".CLV02_B40N_1.SM.GeneralError;
      O     "DB_GRP_62".CLV02_B40N_2.SM.GeneralError;
      O     "DB_GRP_62".CLV02_B25.SM.GeneralError;
      =     "GENERAL_FAULT_GROUP_62";

// GROUP 64
      U     "DB_GRP_64".CLV01_B25.SM.GeneralError;
      O     "DB_GRP_64".CLV02_B25.SM.GeneralError;
      =     "GENERAL_FAULT_GROUP_64";

// GROUP 68
      U     "DB_GRP_68".CLV01_B25.SM.GeneralError;
      =     "GENERAL_FAULT_GROUP_68";

// GROUP 80
      U     "DB_GRP_80".FAN01.SM.GeneralError;
      O     "DB_DIGIT".FM.G80_FAN01;
      O     "DB_VIBRATION_SENSORS".V_80FAN01_A85.SM.GENERAL_ERROR;
      O     "DB_GRP_80".FLA02.SM.GeneralError;
      O     "DB_GRP_80".FAN58.SM.GeneralError;
      O     "DB_GRP_80".FAN58_PRESSURE.SM.GeneralError;
      O     "DB_VIBRATION_SENSORS".V_80FAN58_A85.SM.GENERAL_ERROR;
      O     "DB_GRP_80".FAN61.SM.GeneralError;
      O     "DB_GRP_80".FAN61_PRESSURE.SM.GeneralError;
      O     "DB_VIBRATION_SENSORS".V_80FAN61_A85.SM.GENERAL_ERROR;
      O     "DB_GRP_80".FAN62.SM.GeneralError;
      O     "DB_GRP_80".FAN62_PRESSURE.SM.GeneralError;
      O     "DB_VIBRATION_SENSORS".V_80FAN62_A85.SM.GENERAL_ERROR;
      O     "DB_DIGIT".FM.G80_FAN61_SP_UNREACHABLE;
      O     "DB_DIGIT".FM.G80_FAN62_SP_UNREACHABLE;
      O     "DB_CABINET_R21".SM.GeneralError;
// E-CUBES
      O     "IDB_ECUBE_SCALING_FTR600".QxHH_Alarm;
      O     "IDB_FB_ECUBE_80FTR601".QudtInterface.xCentralizedFault;
      O     "IDB_FB_ECUBE_80FTR602".QudtInterface.xCentralizedFault;
      O     "IDB_FB_ECUBE_80FTR603".QudtInterface.xCentralizedFault;
      O     "IDB_FB_ECUBE_80FTR604".QudtInterface.xCentralizedFault;
      O     "IDB_FB_ECUBE_80FTR605".QudtInterface.xCentralizedFault;
      O     "IDB_FB_ECUBE_80FTR606".QudtInterface.xCentralizedFault;
      O     "IDB_FB_ECUBE_80FTR607".QudtInterface.xCentralizedFault;
      O     "IDB_FB_ECUBE_80FTR608".QudtInterface.xCentralizedFault;
      O     "IDB_FB_ECUBE_80FTR609".QudtInterface.xCentralizedFault;
      O     "IDB_FB_ECUBE_80FTR610".QudtInterface.xCentralizedFault;
      O     "IDB_FB_ECUBE_80FTR611".QudtInterface.xCentralizedFault;
      O     "IDB_FB_ECUBE_80FTR612".QudtInterface.xCentralizedFault;
      O     "IDB_FB_ECUBE_80FTR613".QudtInterface.xCentralizedFault;
      O     "IDB_FB_ECUBE_80FTR614".QudtInterface.xCentralizedFault;
      O     "IDB_FB_ECUBE_80FTR615".QudtInterface.xCentralizedFault;
      O     "IDB_FB_ECUBE_80FTR616".QudtInterface.xCentralizedFault;
      O     "IDB_FB_ECUBE_80FTR617".QudtInterface.xCentralizedFault;
      O     "IDB_FB_ECUBE_80FTR618".QudtInterface.xCentralizedFault;
//      O     "DB_ECUBE_80FTR600_DE".OUT.FM.Change_demand
//      O     "IDB_FB_ECUBE_80FTR601".IudtVisu.FM.b0x6_FillLevelECube_HH
//      O     "IDB_FB_ECUBE_80FTR602".IudtVisu.FM.b0x6_FillLevelECube_HH
//      O     "IDB_FB_ECUBE_80FTR603".IudtVisu.FM.b0x6_FillLevelECube_HH
//      O     "IDB_FB_ECUBE_80FTR604".IudtVisu.FM.b0x6_FillLevelECube_HH
//      O     "IDB_FB_ECUBE_80FTR605".IudtVisu.FM.b0x6_FillLevelECube_HH
//      O     "IDB_FB_ECUBE_80FTR606".IudtVisu.FM.b0x6_FillLevelECube_HH
//      O     "IDB_FB_ECUBE_80FTR607".IudtVisu.FM.b0x6_FillLevelECube_HH
//      O     "IDB_FB_ECUBE_80FTR608".IudtVisu.FM.b0x6_FillLevelECube_HH
//      O     "IDB_FB_ECUBE_80FTR609".IudtVisu.FM.b0x6_FillLevelECube_HH
//      O     "IDB_FB_ECUBE_80FTR610".IudtVisu.FM.b0x6_FillLevelECube_HH
//      O     "IDB_FB_ECUBE_80FTR611".IudtVisu.FM.b0x6_FillLevelECube_HH
//      O     "IDB_FB_ECUBE_80FTR612".IudtVisu.FM.b0x6_FillLevelECube_HH
//      O     "IDB_FB_ECUBE_80FTR613".IudtVisu.FM.b0x6_FillLevelECube_HH
//      O     "IDB_FB_ECUBE_80FTR614".IudtVisu.FM.b0x6_FillLevelECube_HH
//      O     "IDB_FB_ECUBE_80FTR615".IudtVisu.FM.b0x6_FillLevelECube_HH
//      O     "IDB_FB_ECUBE_80FTR616".IudtVisu.FM.b0x6_FillLevelECube_HH
//      O     "IDB_FB_ECUBE_80FTR617".IudtVisu.FM.b0x6_FillLevelECube_HH
//      O     "IDB_FB_ECUBE_80FTR618".IudtVisu.FM.b0x6_FillLevelECube_HH
//      O     "IDB_FB_ECUBE_80FTR601".IudtVisu.FM.b1x0_FillLevel2Filter_HH
//      O     "IDB_FB_ECUBE_80FTR602".IudtVisu.FM.b1x0_FillLevel2Filter_HH
//      O     "IDB_FB_ECUBE_80FTR603".IudtVisu.FM.b1x0_FillLevel2Filter_HH
//      O     "IDB_FB_ECUBE_80FTR604".IudtVisu.FM.b1x0_FillLevel2Filter_HH
//      O     "IDB_FB_ECUBE_80FTR605".IudtVisu.FM.b1x0_FillLevel2Filter_HH
//      O     "IDB_FB_ECUBE_80FTR606".IudtVisu.FM.b1x0_FillLevel2Filter_HH
//      O     "IDB_FB_ECUBE_80FTR607".IudtVisu.FM.b1x0_FillLevel2Filter_HH
//      O     "IDB_FB_ECUBE_80FTR608".IudtVisu.FM.b1x0_FillLevel2Filter_HH
//      O     "IDB_FB_ECUBE_80FTR609".IudtVisu.FM.b1x0_FillLevel2Filter_HH
//      O     "IDB_FB_ECUBE_80FTR610".IudtVisu.FM.b1x0_FillLevel2Filter_HH
//      O     "IDB_FB_ECUBE_80FTR611".IudtVisu.FM.b1x0_FillLevel2Filter_HH
//      O     "IDB_FB_ECUBE_80FTR612".IudtVisu.FM.b1x0_FillLevel2Filter_HH
//      O     "IDB_FB_ECUBE_80FTR613".IudtVisu.FM.b1x0_FillLevel2Filter_HH
//      O     "IDB_FB_ECUBE_80FTR614".IudtVisu.FM.b1x0_FillLevel2Filter_HH
//      O     "IDB_FB_ECUBE_80FTR615".IudtVisu.FM.b1x0_FillLevel2Filter_HH
//      O     "IDB_FB_ECUBE_80FTR616".IudtVisu.FM.b1x0_FillLevel2Filter_HH
//      O     "IDB_FB_ECUBE_80FTR617".IudtVisu.FM.b1x0_FillLevel2Filter_HH
//      O     "IDB_FB_ECUBE_80FTR618".IudtVisu.FM.b1x0_FillLevel2Filter_HH
      =     "GENERAL_FAULT_GR80_R21";

      U     "DB_GRP_80".TAN01_U1.SM.GeneralError;
      O     "DB_GRP_80".TAN01_PRESSURE.SM.GeneralError;
      O     "DB_DIGIT".FM.G80_TAN01_S22;
      O     "DB_DIGIT".FM.G80_TAN01_S21_2;
      O     "DB_DIGIT".FM.G80_TAN01_B32;
      O     "DB_GRP_80".TAN02_U1.SM.GeneralError;
      O     "DB_GRP_80".TAN02_PRESSURE.SM.GeneralError;
      O     "DB_DIGIT".FM.G80_TAN02_S22;
      O     "DB_DIGIT".FM.G80_TAN02_S21_2;
      O     "DB_DIGIT".FM.G80_TAN02_B32;
      O     "DB_GRP_80".FLA60.SM.GeneralError;
      O     "DB_GRP_80".FLA80.SM.GeneralError;
      O     "DB_GRP_80".FLA90.SM.GeneralError;
      O     "DB_GRP_80".FLA97.SM.GeneralError;
      O     "DB_GRP_80".FLA97_M2.SM.GeneralError;
      O     "DB_GRP_80".FAN81.SM.GeneralError;
      O     "DB_GRP_80".FAN81_PRESSURE.SM.GeneralError;
      O     "DB_VIBRATION_SENSORS".V_80FAN81_A85.SM.GENERAL_ERROR;
      O     "DB_GRP_80".FAN91.SM.GeneralError;
      O     "DB_GRP_80".FAN91_PRESSURE.SM.GeneralError;
      O     "DB_VIBRATION_SENSORS".V_80FAN91_A85.SM.GENERAL_ERROR;
      O     "DB_GRP_80".FAN92.SM.GeneralError;
      O     "DB_GRP_80".FAN92_PRESSURE.SM.GeneralError;
      O     "DB_GRP_80".FAN93.SM.GeneralError;
      O     "DB_GRP_80".FAN93_PRESSURE.SM.GeneralError;
      O     "DB_GRP_80".FAN94.SM.GeneralError;
      O     "DB_DIGIT".FM.G80_FAN94_S32F;
      O     "DB_VIBRATION_SENSORS".V_80FAN94_A85.SM.GENERAL_ERROR;
      O     "DB_GRP_80".FAN95.SM.GeneralError;
      O     "DB_GRP_80".FAN95_PRESSURE.SM.GeneralError;
      O     "DB_VIBRATION_SENSORS".V_80FAN95_A85.SM.GENERAL_ERROR;
      O     "DB_DIGIT".FM.G80_FAN81_SP_UNREACHABLE;
      O     "DB_DIGIT".FM.G80_FAN91_SP_UNREACHABLE;
      O     "DB_CABINET_R22".SM.GeneralError;
// E-CUBES
      O     "IDB_ECUBE_SCALING_FTR800".QxHH_Alarm;
      O     "IDB_FB_ECUBE_80FTR801".QudtInterface.xCentralizedFault;
      O     "IDB_FB_ECUBE_80FTR802".QudtInterface.xCentralizedFault;
      O     "IDB_FB_ECUBE_80FTR803".QudtInterface.xCentralizedFault;
      O     "IDB_FB_ECUBE_80FTR804".QudtInterface.xCentralizedFault;
      O     "IDB_FB_ECUBE_80FTR805".QudtInterface.xCentralizedFault;
      O     "IDB_FB_ECUBE_80FTR806".QudtInterface.xCentralizedFault;
      O     "IDB_FB_ECUBE_80FTR807".QudtInterface.xCentralizedFault;
      O     "IDB_FB_ECUBE_80FTR808".QudtInterface.xCentralizedFault;
      O     "IDB_FB_ECUBE_80FTR809".QudtInterface.xCentralizedFault;
      O     "IDB_FB_ECUBE_80FTR810".QudtInterface.xCentralizedFault;
      O     "IDB_ECUBE_SCALING_FTR900".QxHH_Alarm;
      O     "IDB_FB_ECUBE_80FTR901".QudtInterface.xCentralizedFault;
      O     "IDB_FB_ECUBE_80FTR902".QudtInterface.xCentralizedFault;
      O     "IDB_FB_ECUBE_80FTR903".QudtInterface.xCentralizedFault;
      O     "IDB_FB_ECUBE_80FTR904".QudtInterface.xCentralizedFault;
      O     "IDB_FB_ECUBE_80FTR905".QudtInterface.xCentralizedFault;
      O     "IDB_FB_ECUBE_80FTR906".QudtInterface.xCentralizedFault;
//      O     "DB_ECUBE_80FTR800_DE".OUT.FM.Change_demand
//      O     "DB_ECUBE_80FTR900_DE".OUT.FM.Change_demand
//      O     "IDB_FB_ECUBE_80FTR801".IudtVisu.FM.b0x6_FillLevelECube_HH
//      O     "IDB_FB_ECUBE_80FTR802".IudtVisu.FM.b0x6_FillLevelECube_HH
//      O     "IDB_FB_ECUBE_80FTR803".IudtVisu.FM.b0x6_FillLevelECube_HH
//      O     "IDB_FB_ECUBE_80FTR804".IudtVisu.FM.b0x6_FillLevelECube_HH
//      O     "IDB_FB_ECUBE_80FTR805".IudtVisu.FM.b0x6_FillLevelECube_HH
//      O     "IDB_FB_ECUBE_80FTR806".IudtVisu.FM.b0x6_FillLevelECube_HH
//      O     "IDB_FB_ECUBE_80FTR807".IudtVisu.FM.b0x6_FillLevelECube_HH
//      O     "IDB_FB_ECUBE_80FTR808".IudtVisu.FM.b0x6_FillLevelECube_HH
//      O     "IDB_FB_ECUBE_80FTR809".IudtVisu.FM.b0x6_FillLevelECube_HH
//      O     "IDB_FB_ECUBE_80FTR810".IudtVisu.FM.b0x6_FillLevelECube_HH
//      O     "IDB_FB_ECUBE_80FTR901".IudtVisu.FM.b0x6_FillLevelECube_HH
//      O     "IDB_FB_ECUBE_80FTR902".IudtVisu.FM.b0x6_FillLevelECube_HH
//      O     "IDB_FB_ECUBE_80FTR903".IudtVisu.FM.b0x6_FillLevelECube_HH
//      O     "IDB_FB_ECUBE_80FTR904".IudtVisu.FM.b0x6_FillLevelECube_HH
//      O     "IDB_FB_ECUBE_80FTR905".IudtVisu.FM.b0x6_FillLevelECube_HH
//      O     "IDB_FB_ECUBE_80FTR906".IudtVisu.FM.b0x6_FillLevelECube_HH
//      O     "IDB_FB_ECUBE_80FTR801".IudtVisu.FM.b1x0_FillLevel2Filter_HH
//      O     "IDB_FB_ECUBE_80FTR802".IudtVisu.FM.b1x0_FillLevel2Filter_HH
//      O     "IDB_FB_ECUBE_80FTR803".IudtVisu.FM.b1x0_FillLevel2Filter_HH
//      O     "IDB_FB_ECUBE_80FTR804".IudtVisu.FM.b1x0_FillLevel2Filter_HH
//      O     "IDB_FB_ECUBE_80FTR805".IudtVisu.FM.b1x0_FillLevel2Filter_HH
//      O     "IDB_FB_ECUBE_80FTR806".IudtVisu.FM.b1x0_FillLevel2Filter_HH
//      O     "IDB_FB_ECUBE_80FTR807".IudtVisu.FM.b1x0_FillLevel2Filter_HH
//      O     "IDB_FB_ECUBE_80FTR808".IudtVisu.FM.b1x0_FillLevel2Filter_HH
//      O     "IDB_FB_ECUBE_80FTR809".IudtVisu.FM.b1x0_FillLevel2Filter_HH
//      O     "IDB_FB_ECUBE_80FTR810".IudtVisu.FM.b1x0_FillLevel2Filter_HH
//      O     "IDB_FB_ECUBE_80FTR901".IudtVisu.FM.b1x0_FillLevel2Filter_HH
//      O     "IDB_FB_ECUBE_80FTR902".IudtVisu.FM.b1x0_FillLevel2Filter_HH
//      O     "IDB_FB_ECUBE_80FTR903".IudtVisu.FM.b1x0_FillLevel2Filter_HH
//      O     "IDB_FB_ECUBE_80FTR904".IudtVisu.FM.b1x0_FillLevel2Filter_HH
//      O     "IDB_FB_ECUBE_80FTR905".IudtVisu.FM.b1x0_FillLevel2Filter_HH
//      O     "IDB_FB_ECUBE_80FTR906".IudtVisu.FM.b1x0_FillLevel2Filter_HH
      =     "GENERAL_FAULT_GR80_R22";

// GROUP 81
      U     "DB_DIGIT".FM.G81_DOO08;
      O     "DB_GRP_81".FLA11.SM.GeneralError;
      O     "DB_GRP_81".FLA12.SM.GeneralError;
      O     "DB_GRP_81".FLA13.SM.GeneralError;
      O     "DB_GRP_81".FLA14.SM.GeneralError;
      O     "DB_GRP_81".FTR20.SM.GeneralError;
      O     "DB_GRP_81".PP30.SM.GeneralError;
      O     "DB_GRP_81".PP31.SM.GeneralError;
      O     "DB_GRP_81".VA31.SM.GeneralError;
      O     "DB_GRP_81".CLT32.SM.GeneralError;
      O     "DB_DIGIT".FM.G81_MT33;
      O     "DB_DIGIT".FM.G81_MT34_A41_L2;
      O     "DB_DIGIT".FM.G81_MT34_1_L2;
      O     "DB_GRP_81".PP40.SM.GeneralError;
      O     "DB_GRP_81".VA41_M1.SM.GeneralError;
      O     "DB_GRP_81".VA41_M2.SM.GeneralError;
      O     "DB_GRP_81".PP50.SM.GeneralError;
      O     "DB_GRP_81".PP51.SM.GeneralError;
      O     "DB_GRP_81".VA51.SM.GeneralError;
      O     "DB_DIGIT".FM.G81_MT53;
      O     "DB_DIGIT".FM.G81_FIL63_B22_1;
      O     "DB_DIGIT".FM.G81_FIL63_B21;
      O     "DB_GRP_81".PP61.SM.GeneralError;
      O     "DB_VIBRATION_SENSORS".V_81PP61_A85.SM.GENERAL_ERROR;
      O     "DB_GRP_81".FIL63_Y1.SM.GeneralError;
      O     "DB_GRP_81".FTR80.SM.GeneralError;
      O     "DB_GRP_81".CLT81.SM.GeneralError;
      O     "DB_GRP_81".CLM82_HUM.SM.GeneralError;
      O     "DB_GRP_81".CLM82_TEMP.SM.GeneralError;
      O     "DB_CABINET_R27".SM.GeneralError;
      O     "DB_DIGIT".FM.G81_FIL63_PLAUS;
      O     "DB_DIGIT".FM.G81_MT34_A41_PLAUS;
      O     "DB_DIGIT".FM.G81_MT34_1_PLAUS;
      O     "DB_DIGIT".FM.G81_CLV63_PILOTCONT;
      =     "GENERAL_FAULT_GR81_R27";

      U     "DB_GRP_81".FAN71.SM.GeneralError;
      O     "DB_DIGIT".FM.G81_FAN71;
      O     "DB_VIBRATION_SENSORS".V_81FAN71_A85.SM.GENERAL_ERROR;
      O     "DB_CABINET_R28".SM.GeneralError;
      =     "GENERAL_FAULT_GR81_R28";

      U     "DB_GRP_81".FAN72.SM.GeneralError;
      O     "DB_DIGIT".FM.G81_FAN72;
      O     "DB_VIBRATION_SENSORS".V_81FAN72_A85.SM.GENERAL_ERROR;
      O     "DB_CABINET_R29".SM.GeneralError;
      =     "GENERAL_FAULT_GR81_R29";

// GROUP 82
      U     "DB_GRP_82".FTR20.SM.GeneralError;
      O     "DB_DIGIT".FM.G82_MO21_B511_ALARM;
      O     "DB_GRP_82".MO21_B51_1.SM.GeneralError;
      O     "DB_DIGIT".FM.G82_MO21_B512_ALARM;
      O     "DB_GRP_82".MO21_B51_2.SM.GeneralError;
      O     "DB_GRP_82".CLM82_HUM.SM.GeneralError;
      O     "DB_GRP_82".CLM82_TEMP.SM.GeneralError;
      O     "DB_GRP_82".CLT81.SM.GeneralError;
      O     "DB_GRP_82".PP40.SM.GeneralError;
      O     "DB_GRP_82".VA41.SM.GeneralError;
      O     "DB_GRP_82".FTR80.SM.GeneralError;
      O     "DB_GRP_82".FAN91.SM.GeneralError;
      O     "DB_GRP_82".FAN91_PRESSURE.SM.GeneralError;
      O     "DB_VIBRATION_SENSORS".V_82FAN91_A85.SM.GENERAL_ERROR;
      O     "DB_GRP_82".FAN92.SM.GeneralError;
      O     "DB_GRP_82".FAN92_PRESSURE.SM.GeneralError;
      O     "DB_VIBRATION_SENSORS".V_82FAN92_A85.SM.GENERAL_ERROR;
      O     "DB_CABINET_R23".SM.GeneralError;
      =     "GENERAL_FAULT_GR82";

// GROUP 83
      U     "DB_GRP_83".FTR20.SM.GeneralError;
      O     "DB_DIGIT".FM.G83_MO21_B511_ALARM;
      O     "DB_GRP_83".MO21_B51_1.SM.GeneralError;
      O     "DB_DIGIT".FM.G83_MO21_B512_ALARM;
      O     "DB_GRP_83".MO21_B51_2.SM.GeneralError;
      O     "DB_GRP_83".PP50.SM.GeneralError;
      O     "DB_GRP_83".PP51.SM.GeneralError;
      O     "DB_GRP_83".VA51.SM.GeneralError;
      O     "DB_DIGIT".FM.G83_MT53;
      O     "DB_GRP_83".FTR80.SM.GeneralError;
      O     "DB_GRP_83".CLT81.SM.GeneralError;
      O     "DB_GRP_83".FAN91.SM.GeneralError;
      O     "DB_GRP_83".FAN91_PRESSURE.SM.GeneralError;
      O     "DB_VIBRATION_SENSORS".V_83FAN91_A85.SM.GENERAL_ERROR;
      O     "DB_CABINET_R24".SM.GeneralError;
      =     "GENERAL_FAULT_GR83";

NETWORK
TITLE =GENERAL WARNINGS
//********************************************************************************
//
//                              GENERAL WARNINGS
//
//********************************************************************************
//
//
//
//UNBLOCK E-CUBE CHANGE DEMAND AND FILLING LEVEL WARNINGS IF PROBLEM WITH FILLING
//LEVEL CALCULATIONS IS FIXED
// GROUP 61
      U     "DB_GRP_61".CLV02_B40N_1.SM.GeneralWarning;
      O     "DB_GRP_61".CLV02_B40N_2.SM.GeneralWarning;
      O     "DB_GRP_61".CLV02_B25.SM.GeneralWarning;
      =     "GENERAL_FAULT_GROUP_61";

// GROUP 62
      U     "DB_GRP_62".CLV01_B40N_1.SM.GeneralWarning;
      O     "DB_GRP_62".CLV01_B40N_2.SM.GeneralWarning;
      O     "DB_GRP_62".CLV01_B25.SM.GeneralWarning;
      O     "DB_GRP_62".CLV02_B40N_1.SM.GeneralWarning;
      O     "DB_GRP_62".CLV02_B40N_2.SM.GeneralWarning;
      O     "DB_GRP_62".CLV02_B25.SM.GeneralWarning;
      =     "GENERAL_FAULT_GROUP_62";

// GROUP 64
      U     "DB_GRP_64".CLV01_B25.SM.GeneralWarning;
      O     "DB_GRP_64".CLV02_B25.SM.GeneralWarning;
      =     "GENERAL_FAULT_GROUP_64";

// GROUP 68
      U     "DB_GRP_68".CLV01_B25.SM.GeneralWarning;
      =     "GENERAL_FAULT_GROUP_68";

// GROUP 80
      U     "DB_GRP_80".FAN01.SM.GeneralWarning;
      O     "DB_VIBRATION_SENSORS".V_80FAN01_A85.FM.PRE_ALARM;
      O     "DB_GRP_80".FLA02.SM.GeneralWarning;
      O     "DB_GRP_80".FAN58.SM.GeneralWarning;
      O     "DB_GRP_80".FAN58_PRESSURE.SM.GeneralWarning;
      O     "DB_VIBRATION_SENSORS".V_80FAN58_A85.FM.PRE_ALARM;
      O     "DB_GRP_80".FAN61.SM.GeneralWarning;
      O     "DB_GRP_80".FAN61_PRESSURE.SM.GeneralWarning;
      O     "DB_VIBRATION_SENSORS".V_80FAN61_A85.FM.PRE_ALARM;
      O     "DB_GRP_80".FAN62.SM.GeneralWarning;
      O     "DB_GRP_80".FAN62_PRESSURE.SM.GeneralWarning;
      O     "DB_VIBRATION_SENSORS".V_80FAN62_A85.FM.PRE_ALARM;
// E-CUBES

      O     "IDB_FB_ECUBE_80FTR601".QudtInterface.xCentralizedWarning;
      O     "IDB_FB_ECUBE_80FTR602".QudtInterface.xCentralizedWarning;
      O     "IDB_FB_ECUBE_80FTR603".QudtInterface.xCentralizedWarning;
      O     "IDB_FB_ECUBE_80FTR604".QudtInterface.xCentralizedWarning;
      O     "IDB_FB_ECUBE_80FTR605".QudtInterface.xCentralizedWarning;
      O     "IDB_FB_ECUBE_80FTR606".QudtInterface.xCentralizedWarning;
      O     "IDB_FB_ECUBE_80FTR607".QudtInterface.xCentralizedWarning;
      O     "IDB_FB_ECUBE_80FTR608".QudtInterface.xCentralizedWarning;
      O     "IDB_FB_ECUBE_80FTR609".QudtInterface.xCentralizedWarning;
      O     "IDB_FB_ECUBE_80FTR610".QudtInterface.xCentralizedWarning;
      O     "IDB_FB_ECUBE_80FTR611".QudtInterface.xCentralizedWarning;
      O     "IDB_FB_ECUBE_80FTR612".QudtInterface.xCentralizedWarning;
      O     "IDB_FB_ECUBE_80FTR613".QudtInterface.xCentralizedWarning;
      O     "IDB_FB_ECUBE_80FTR614".QudtInterface.xCentralizedWarning;
      O     "IDB_FB_ECUBE_80FTR615".QudtInterface.xCentralizedWarning;
      O     "IDB_FB_ECUBE_80FTR616".QudtInterface.xCentralizedWarning;
      O     "IDB_FB_ECUBE_80FTR617".QudtInterface.xCentralizedWarning;
      O     "IDB_FB_ECUBE_80FTR618".QudtInterface.xCentralizedWarning;

      O     "DB_ECUBE_80FTR600_DE".OUT.FM.FTR601_Replace_time;
      O     "DB_ECUBE_80FTR600_DE".OUT.FM.FTR602_Replace_time;
      O     "DB_ECUBE_80FTR600_DE".OUT.FM.FTR603_Replace_time;
      O     "DB_ECUBE_80FTR600_DE".OUT.FM.FTR604_Replace_time;
      O     "DB_ECUBE_80FTR600_DE".OUT.FM.FTR605_Replace_time;
      O     "DB_ECUBE_80FTR600_DE".OUT.FM.FTR606_Replace_time;
      O     "DB_ECUBE_80FTR600_DE".OUT.FM.FTR607_Replace_time;
      O     "DB_ECUBE_80FTR600_DE".OUT.FM.FTR608_Replace_time;
      O     "DB_ECUBE_80FTR600_DE".OUT.FM.FTR609_Replace_time;
      O     "DB_ECUBE_80FTR600_DE".OUT.FM.FTR610_Replace_time;
      O     "DB_ECUBE_80FTR600_DE".OUT.FM.FTR611_Replace_time;
      O     "DB_ECUBE_80FTR600_DE".OUT.FM.FTR612_Replace_time;
      O     "DB_ECUBE_80FTR600_DE".OUT.FM.FTR613_Replace_time;
      O     "DB_ECUBE_80FTR600_DE".OUT.FM.FTR614_Replace_time;
      O     "DB_ECUBE_80FTR600_DE".OUT.FM.FTR615_Replace_time;
      O     "DB_ECUBE_80FTR600_DE".OUT.FM.FTR616_Replace_time;
      O     "DB_ECUBE_80FTR600_DE".OUT.FM.FTR617_Replace_time;
      O     "DB_ECUBE_80FTR600_DE".OUT.FM.FTR618_Replace_time;
//      O     "IDB_FB_ECUBE_80FTR601".IudtVisu.FM.b0x6_FillLevelECube_H
//      O     "IDB_FB_ECUBE_80FTR602".IudtVisu.FM.b0x6_FillLevelECube_H
//      O     "IDB_FB_ECUBE_80FTR603".IudtVisu.FM.b0x6_FillLevelECube_H
//      O     "IDB_FB_ECUBE_80FTR604".IudtVisu.FM.b0x6_FillLevelECube_H
//      O     "IDB_FB_ECUBE_80FTR605".IudtVisu.FM.b0x6_FillLevelECube_H
//      O     "IDB_FB_ECUBE_80FTR606".IudtVisu.FM.b0x6_FillLevelECube_H
//      O     "IDB_FB_ECUBE_80FTR607".IudtVisu.FM.b0x6_FillLevelECube_H
//      O     "IDB_FB_ECUBE_80FTR608".IudtVisu.FM.b0x6_FillLevelECube_H
//      O     "IDB_FB_ECUBE_80FTR609".IudtVisu.FM.b0x6_FillLevelECube_H
//      O     "IDB_FB_ECUBE_80FTR610".IudtVisu.FM.b0x6_FillLevelECube_H
//      O     "IDB_FB_ECUBE_80FTR611".IudtVisu.FM.b0x6_FillLevelECube_H
//      O     "IDB_FB_ECUBE_80FTR612".IudtVisu.FM.b0x6_FillLevelECube_H
//      O     "IDB_FB_ECUBE_80FTR613".IudtVisu.FM.b0x6_FillLevelECube_H
//      O     "IDB_FB_ECUBE_80FTR614".IudtVisu.FM.b0x6_FillLevelECube_H
//      O     "IDB_FB_ECUBE_80FTR615".IudtVisu.FM.b0x6_FillLevelECube_H
//      O     "IDB_FB_ECUBE_80FTR616".IudtVisu.FM.b0x6_FillLevelECube_H
//      O     "IDB_FB_ECUBE_80FTR617".IudtVisu.FM.b0x6_FillLevelECube_H
//      O     "IDB_FB_ECUBE_80FTR618".IudtVisu.FM.b0x6_FillLevelECube_H
//      O     "IDB_FB_ECUBE_80FTR601".IudtVisu.FM.b1x0_FillLevel2Filter_H
//      O     "IDB_FB_ECUBE_80FTR602".IudtVisu.FM.b1x0_FillLevel2Filter_H
//      O     "IDB_FB_ECUBE_80FTR603".IudtVisu.FM.b1x0_FillLevel2Filter_H
//      O     "IDB_FB_ECUBE_80FTR604".IudtVisu.FM.b1x0_FillLevel2Filter_H
//      O     "IDB_FB_ECUBE_80FTR605".IudtVisu.FM.b1x0_FillLevel2Filter_H
//      O     "IDB_FB_ECUBE_80FTR606".IudtVisu.FM.b1x0_FillLevel2Filter_H
//      O     "IDB_FB_ECUBE_80FTR607".IudtVisu.FM.b1x0_FillLevel2Filter_H
//      O     "IDB_FB_ECUBE_80FTR608".IudtVisu.FM.b1x0_FillLevel2Filter_H
//      O     "IDB_FB_ECUBE_80FTR609".IudtVisu.FM.b1x0_FillLevel2Filter_H
//      O     "IDB_FB_ECUBE_80FTR610".IudtVisu.FM.b1x0_FillLevel2Filter_H
//      O     "IDB_FB_ECUBE_80FTR611".IudtVisu.FM.b1x0_FillLevel2Filter_H
//      O     "IDB_FB_ECUBE_80FTR612".IudtVisu.FM.b1x0_FillLevel2Filter_H
//      O     "IDB_FB_ECUBE_80FTR613".IudtVisu.FM.b1x0_FillLevel2Filter_H
//      O     "IDB_FB_ECUBE_80FTR614".IudtVisu.FM.b1x0_FillLevel2Filter_H
//      O     "IDB_FB_ECUBE_80FTR615".IudtVisu.FM.b1x0_FillLevel2Filter_H
//      O     "IDB_FB_ECUBE_80FTR616".IudtVisu.FM.b1x0_FillLevel2Filter_H
//      O     "IDB_FB_ECUBE_80FTR617".IudtVisu.FM.b1x0_FillLevel2Filter_H
//      O     "IDB_FB_ECUBE_80FTR618".IudtVisu.FM.b1x0_FillLevel2Filter_H

      O     "DB_CABINET_R21".SM.GeneralWarning;
      =     "WARNING_GR80_R21";

      U     "DB_GRP_80".TAN01_U1.SM.GeneralWarning;
      ON    "DB_DIGIT".SM.G80_TAN01_S21_1;
      O     "DB_GRP_80".TAN02_U1.SM.GeneralWarning;
      ON    "DB_DIGIT".SM.G80_TAN02_S21_1;
      O     "DB_GRP_80".FLA60.SM.GeneralWarning;
      O     "DB_GRP_80".FLA80.SM.GeneralWarning;
      O     "DB_GRP_80".FLA90.SM.GeneralWarning;
      O     "DB_GRP_80".FLA97.SM.GeneralWarning;
      O     "DB_GRP_80".FLA97_M2.SM.GeneralWarning;
      O     "DB_GRP_80".FAN81.SM.GeneralWarning;
      O     "DB_GRP_80".FAN81_PRESSURE.SM.GeneralWarning;
      O     "DB_VIBRATION_SENSORS".V_80FAN81_A85.FM.PRE_ALARM;
      O     "DB_GRP_80".FAN91.SM.GeneralWarning;
      O     "DB_GRP_80".FAN91_PRESSURE.SM.GeneralWarning;
      O     "DB_VIBRATION_SENSORS".V_80FAN91_A85.FM.PRE_ALARM;
      O     "DB_GRP_80".FAN92.SM.GeneralWarning;
      O     "DB_GRP_80".FAN92_PRESSURE.SM.GeneralWarning;
      O     "DB_GRP_80".FAN93.SM.GeneralWarning;
      O     "DB_GRP_80".FAN93_PRESSURE.SM.GeneralWarning;
      O     "DB_GRP_80".FAN94.SM.GeneralWarning;
      O     "DB_VIBRATION_SENSORS".V_80FAN94_A85.FM.PRE_ALARM;
      O     "DB_GRP_80".FAN95.SM.GeneralWarning;
      O     "DB_GRP_80".FAN95_PRESSURE.SM.GeneralWarning;
      O     "DB_VIBRATION_SENSORS".V_80FAN95_A85.FM.PRE_ALARM;
// E-CUBES
      O     "IDB_FB_ECUBE_80FTR801".QudtInterface.xCentralizedWarning;
      O     "IDB_FB_ECUBE_80FTR802".QudtInterface.xCentralizedWarning;
      O     "IDB_FB_ECUBE_80FTR803".QudtInterface.xCentralizedWarning;
      O     "IDB_FB_ECUBE_80FTR804".QudtInterface.xCentralizedWarning;
      O     "IDB_FB_ECUBE_80FTR805".QudtInterface.xCentralizedWarning;
      O     "IDB_FB_ECUBE_80FTR806".QudtInterface.xCentralizedWarning;
      O     "IDB_FB_ECUBE_80FTR807".QudtInterface.xCentralizedWarning;
      O     "IDB_FB_ECUBE_80FTR808".QudtInterface.xCentralizedWarning;
      O     "IDB_FB_ECUBE_80FTR809".QudtInterface.xCentralizedWarning;
      O     "IDB_FB_ECUBE_80FTR810".QudtInterface.xCentralizedWarning;
      O     "IDB_FB_ECUBE_80FTR901".QudtInterface.xCentralizedWarning;
      O     "IDB_FB_ECUBE_80FTR902".QudtInterface.xCentralizedWarning;
      O     "IDB_FB_ECUBE_80FTR903".QudtInterface.xCentralizedWarning;
      O     "IDB_FB_ECUBE_80FTR904".QudtInterface.xCentralizedWarning;
      O     "IDB_FB_ECUBE_80FTR905".QudtInterface.xCentralizedWarning;
      O     "IDB_FB_ECUBE_80FTR906".QudtInterface.xCentralizedWarning;
      O     "DB_ECUBE_80FTR800_DE".OUT.FM.FTR801_Replace_time;
      O     "DB_ECUBE_80FTR800_DE".OUT.FM.FTR802_Replace_time;
      O     "DB_ECUBE_80FTR800_DE".OUT.FM.FTR803_Replace_time;
      O     "DB_ECUBE_80FTR800_DE".OUT.FM.FTR804_Replace_time;
      O     "DB_ECUBE_80FTR800_DE".OUT.FM.FTR805_Replace_time;
      O     "DB_ECUBE_80FTR800_DE".OUT.FM.FTR806_Replace_time;
      O     "DB_ECUBE_80FTR800_DE".OUT.FM.FTR807_Replace_time;
      O     "DB_ECUBE_80FTR800_DE".OUT.FM.FTR808_Replace_time;
      O     "DB_ECUBE_80FTR800_DE".OUT.FM.FTR809_Replace_time;
      O     "DB_ECUBE_80FTR800_DE".OUT.FM.FTR810_Replace_time;
      O     "DB_ECUBE_80FTR900_DE".OUT.FM.FTR901_Replace_time;
      O     "DB_ECUBE_80FTR900_DE".OUT.FM.FTR902_Replace_time;
      O     "DB_ECUBE_80FTR900_DE".OUT.FM.FTR903_Replace_time;
      O     "DB_ECUBE_80FTR900_DE".OUT.FM.FTR904_Replace_time;
      O     "DB_ECUBE_80FTR900_DE".OUT.FM.FTR905_Replace_time;
      O     "DB_ECUBE_80FTR900_DE".OUT.FM.FTR906_Replace_time;
//      O     "IDB_FB_ECUBE_80FTR801".IudtVisu.FM.b0x6_FillLevelECube_H
//      O     "IDB_FB_ECUBE_80FTR802".IudtVisu.FM.b0x6_FillLevelECube_H
//      O     "IDB_FB_ECUBE_80FTR803".IudtVisu.FM.b0x6_FillLevelECube_H
//      O     "IDB_FB_ECUBE_80FTR804".IudtVisu.FM.b0x6_FillLevelECube_H
//      O     "IDB_FB_ECUBE_80FTR805".IudtVisu.FM.b0x6_FillLevelECube_H
//      O     "IDB_FB_ECUBE_80FTR806".IudtVisu.FM.b0x6_FillLevelECube_H
//      O     "IDB_FB_ECUBE_80FTR807".IudtVisu.FM.b0x6_FillLevelECube_H
//      O     "IDB_FB_ECUBE_80FTR808".IudtVisu.FM.b0x6_FillLevelECube_H
//      O     "IDB_FB_ECUBE_80FTR809".IudtVisu.FM.b0x6_FillLevelECube_H
//      O     "IDB_FB_ECUBE_80FTR810".IudtVisu.FM.b0x6_FillLevelECube_H
//      O     "IDB_FB_ECUBE_80FTR901".IudtVisu.FM.b0x6_FillLevelECube_H
//      O     "IDB_FB_ECUBE_80FTR902".IudtVisu.FM.b0x6_FillLevelECube_H
//      O     "IDB_FB_ECUBE_80FTR903".IudtVisu.FM.b0x6_FillLevelECube_H
//      O     "IDB_FB_ECUBE_80FTR904".IudtVisu.FM.b0x6_FillLevelECube_H
//      O     "IDB_FB_ECUBE_80FTR905".IudtVisu.FM.b0x6_FillLevelECube_H
//      O     "IDB_FB_ECUBE_80FTR906".IudtVisu.FM.b0x6_FillLevelECube_H
//      O     "IDB_FB_ECUBE_80FTR801".IudtVisu.FM.b1x0_FillLevel2Filter_H
//      O     "IDB_FB_ECUBE_80FTR802".IudtVisu.FM.b1x0_FillLevel2Filter_H
//      O     "IDB_FB_ECUBE_80FTR803".IudtVisu.FM.b1x0_FillLevel2Filter_H
//      O     "IDB_FB_ECUBE_80FTR804".IudtVisu.FM.b1x0_FillLevel2Filter_H
//      O     "IDB_FB_ECUBE_80FTR805".IudtVisu.FM.b1x0_FillLevel2Filter_H
//      O     "IDB_FB_ECUBE_80FTR806".IudtVisu.FM.b1x0_FillLevel2Filter_H
//      O     "IDB_FB_ECUBE_80FTR807".IudtVisu.FM.b1x0_FillLevel2Filter_H
//      O     "IDB_FB_ECUBE_80FTR808".IudtVisu.FM.b1x0_FillLevel2Filter_H
//      O     "IDB_FB_ECUBE_80FTR809".IudtVisu.FM.b1x0_FillLevel2Filter_H
//      O     "IDB_FB_ECUBE_80FTR810".IudtVisu.FM.b1x0_FillLevel2Filter_H
//      O     "IDB_FB_ECUBE_80FTR901".IudtVisu.FM.b1x0_FillLevel2Filter_H
//      O     "IDB_FB_ECUBE_80FTR902".IudtVisu.FM.b1x0_FillLevel2Filter_H
//      O     "IDB_FB_ECUBE_80FTR903".IudtVisu.FM.b1x0_FillLevel2Filter_H
//      O     "IDB_FB_ECUBE_80FTR904".IudtVisu.FM.b1x0_FillLevel2Filter_H
//      O     "IDB_FB_ECUBE_80FTR905".IudtVisu.FM.b1x0_FillLevel2Filter_H
//      O     "IDB_FB_ECUBE_80FTR906".IudtVisu.FM.b1x0_FillLevel2Filter_H

      O     "DB_CABINET_R22".SM.GeneralWarning;
      =     "WARNING_GR80_R22";

// GROUP 81
      U     "DB_GRP_81".FLA11.SM.GeneralWarning;
      O     "DB_GRP_81".FLA12.SM.GeneralWarning;
      O     "DB_GRP_81".FLA13.SM.GeneralWarning;
      O     "DB_GRP_81".FLA14.SM.GeneralWarning;
      O     "DB_GRP_81".FTR20.SM.GeneralWarning;
      O     "DB_GRP_81".PP30.SM.GeneralWarning;
      O     "DB_GRP_81".PP31.SM.GeneralWarning;
      O     "DB_GRP_81".VA31.SM.GeneralWarning;
      O     "DB_GRP_81".CLT32.SM.GeneralWarning;
      O     "DB_DIGIT".FM.G81_MT34_A41_L1;
      O     "DB_DIGIT".FM.G81_MT34_1_L1;
      O     "DB_DIGIT".FM.G81_MT34_A41_PLAUS;
      O     "DB_DIGIT".FM.G81_MT34_1_PLAUS;
      O     "DB_GRP_81".PP40.SM.GeneralWarning;
      O     "DB_GRP_81".VA41_M1.SM.GeneralWarning;
      O     "DB_GRP_81".VA41_M2.SM.GeneralWarning;
      O     "DB_GRP_81".PP50.SM.GeneralWarning;
      O     "DB_GRP_81".PP51.SM.GeneralWarning;
      O     "DB_GRP_81".VA51.SM.GeneralWarning;
      O     "DB_DIGIT".FM.G81_FIL63_B22;
      O     "DB_DIGIT".FM.G81_FIL63_PLAUS;
      O     "DB_GRP_81".PP61.SM.GeneralWarning;
      O     "DB_VIBRATION_SENSORS".V_81PP61_A85.FM.PRE_ALARM;
      O     "DB_GRP_81".FIL63_Y1.SM.GeneralWarning;
      O     "DB_GRP_81".FTR80.SM.GeneralWarning;
      O     "DB_GRP_81".CLT81.SM.GeneralWarning;
      O     "DB_GRP_81".CLM82_HUM.SM.GeneralWarning;
      O     "DB_GRP_81".CLM82_TEMP.SM.GeneralWarning;
      O     "DB_CABINET_R27".SM.GeneralWarning;
      =     "WARNING_GR81_R27";

      U     "DB_GRP_81".FAN71.SM.GeneralWarning;
      O     "DB_VIBRATION_SENSORS".V_81FAN71_A85.FM.PRE_ALARM;
      O     "DB_CABINET_R28".SM.GeneralWarning;
      =     "WARNING_GR81_R28";

      U     "DB_GRP_81".FAN72.SM.GeneralWarning;
      O     "DB_VIBRATION_SENSORS".V_81FAN72_A85.FM.PRE_ALARM;
      O     "DB_CABINET_R29".SM.GeneralWarning;
      =     "WARNING_GR81_R29";

// GROUP 82
      U     "DB_GRP_82".FTR20.SM.GeneralWarning;
      O     "DB_DIGIT".FM.G83_MO21_B511_PREALARM;
      O     "DB_GRP_82".MO21_B51_1.SM.GeneralWarning;
      O     "DB_DIGIT".FM.G83_MO21_B512_PREALARM;
      O     "DB_DIGIT".FM.G83_MO21_PLAUS_WARNING;
      O     "DB_GRP_82".MO21_B51_2.SM.GeneralWarning;
      O     "DB_GRP_82".CLM82_HUM.SM.GeneralWarning;
      O     "DB_GRP_82".CLM82_TEMP.SM.GeneralWarning;
      O     "DB_GRP_82".CLT81.SM.GeneralWarning;
      O     "DB_GRP_82".PP40.SM.GeneralWarning;
      O     "DB_GRP_82".VA41.SM.GeneralWarning;
      O     "DB_GRP_82".FTR80.SM.GeneralWarning;
      O     "DB_GRP_82".FAN91.SM.GeneralWarning;
      O     "DB_GRP_82".FAN91_PRESSURE.SM.GeneralWarning;
      O     "DB_VIBRATION_SENSORS".V_82FAN91_A85.FM.PRE_ALARM;
      O     "DB_GRP_82".FAN92.SM.GeneralWarning;
      O     "DB_GRP_82".FAN92_PRESSURE.SM.GeneralWarning;
      O     "DB_VIBRATION_SENSORS".V_82FAN92_A85.FM.PRE_ALARM;
      O     "DB_CABINET_R23".SM.GeneralWarning;
      =     "WARNING_GR82";

// GROUP 83
      U     "DB_GRP_83".FTR20.SM.GeneralWarning;
      O     "DB_DIGIT".FM.G83_MO21_B511_PREALARM;
      O     "DB_GRP_83".MO21_B51_1.SM.GeneralWarning;
      O     "DB_DIGIT".FM.G83_MO21_B512_PREALARM;
      O     "DB_DIGIT".FM.G83_MO21_PLAUS_WARNING;
      O     "DB_GRP_83".MO21_B51_2.SM.GeneralWarning;
      O     "DB_GRP_83".PP50.SM.GeneralWarning;
      O     "DB_GRP_83".PP51.SM.GeneralWarning;
      O     "DB_GRP_83".VA51.SM.GeneralWarning;
      O     "DB_GRP_83".FTR80.SM.GeneralWarning;
      O     "DB_GRP_83".CLT81.SM.GeneralWarning;
      O     "DB_GRP_83".FAN91.SM.GeneralWarning;
      O     "DB_GRP_83".FAN91_PRESSURE.SM.GeneralWarning;
      O     "DB_VIBRATION_SENSORS".V_83FAN91_A85.FM.PRE_ALARM;
      O     "DB_CABINET_R24".SM.GeneralWarning;
      =     "WARNING_GR83";

NETWORK
TITLE =MANUAL MODE
//********************************************************************************
//
//                                MANUAL MODE
//
//********************************************************************************
//
// GROUP 80
      U     "DB_GRP_80".FAN01.SM.ManualMode;
      O     "DB_GRP_80".FLA02.SM.ManualMode;
      O     "DB_GRP_80".FAN58.SM.ManualMode;
      O     "DB_GRP_80".FAN61.SM.ManualMode;
      O     "DB_GRP_80".FAN62.SM.ManualMode;
// E-CUBES
      O     "IDB_FB_ECUBE_80FTR601".IudtVisu.SM.b0x1_Manual;
      O     "IDB_FB_ECUBE_80FTR602".IudtVisu.SM.b0x1_Manual;
      O     "IDB_FB_ECUBE_80FTR603".IudtVisu.SM.b0x1_Manual;
      O     "IDB_FB_ECUBE_80FTR604".IudtVisu.SM.b0x1_Manual;
      O     "IDB_FB_ECUBE_80FTR605".IudtVisu.SM.b0x1_Manual;
      O     "IDB_FB_ECUBE_80FTR606".IudtVisu.SM.b0x1_Manual;
      O     "IDB_FB_ECUBE_80FTR607".IudtVisu.SM.b0x1_Manual;
      O     "IDB_FB_ECUBE_80FTR608".IudtVisu.SM.b0x1_Manual;
      O     "IDB_FB_ECUBE_80FTR609".IudtVisu.SM.b0x1_Manual;
      O     "IDB_FB_ECUBE_80FTR610".IudtVisu.SM.b0x1_Manual;
      O     "IDB_FB_ECUBE_80FTR611".IudtVisu.SM.b0x1_Manual;
      O     "IDB_FB_ECUBE_80FTR612".IudtVisu.SM.b0x1_Manual;
      O     "IDB_FB_ECUBE_80FTR613".IudtVisu.SM.b0x1_Manual;
      O     "IDB_FB_ECUBE_80FTR614".IudtVisu.SM.b0x1_Manual;
      O     "IDB_FB_ECUBE_80FTR615".IudtVisu.SM.b0x1_Manual;
      O     "IDB_FB_ECUBE_80FTR616".IudtVisu.SM.b0x1_Manual;
      O     "IDB_FB_ECUBE_80FTR617".IudtVisu.SM.b0x1_Manual;
      O     "IDB_FB_ECUBE_80FTR618".IudtVisu.SM.b0x1_Manual;
      =     "MANUAL_GR80_R21";

      U     "DB_GRP_80".TAN01_U1.SM.ManualMode;
      O     "DB_GRP_80".TAN02_U1.SM.ManualMode;
      O     "DB_GRP_80".FLA60.SM.ManualMode;
      O     "DB_GRP_80".FLA80.SM.ManualMode;
      O     "DB_GRP_80".FLA90.SM.ManualMode;
      O     "DB_GRP_80".FLA97.SM.ManualMode;
      O     "DB_GRP_80".FLA97_M2.SM.ManualMode;
      O     "DB_GRP_80".FAN81.SM.ManualMode;
      O     "DB_GRP_80".FAN91.SM.ManualMode;
      O     "DB_GRP_80".FAN92.SM.ManualMode;
      O     "DB_GRP_80".FAN93.SM.ManualMode;
      O     "DB_GRP_80".FAN94.SM.ManualMode;
      O     "DB_GRP_80".FAN95.SM.ManualMode;
// E-CUBES
      O     "IDB_FB_ECUBE_80FTR801".IudtVisu.SM.b0x1_Manual;
      O     "IDB_FB_ECUBE_80FTR802".IudtVisu.SM.b0x1_Manual;
      O     "IDB_FB_ECUBE_80FTR803".IudtVisu.SM.b0x1_Manual;
      O     "IDB_FB_ECUBE_80FTR804".IudtVisu.SM.b0x1_Manual;
      O     "IDB_FB_ECUBE_80FTR805".IudtVisu.SM.b0x1_Manual;
      O     "IDB_FB_ECUBE_80FTR806".IudtVisu.SM.b0x1_Manual;
      O     "IDB_FB_ECUBE_80FTR807".IudtVisu.SM.b0x1_Manual;
      O     "IDB_FB_ECUBE_80FTR808".IudtVisu.SM.b0x1_Manual;
      O     "IDB_FB_ECUBE_80FTR809".IudtVisu.SM.b0x1_Manual;
      O     "IDB_FB_ECUBE_80FTR810".IudtVisu.SM.b0x1_Manual;
      O     "IDB_FB_ECUBE_80FTR901".IudtVisu.SM.b0x1_Manual;
      O     "IDB_FB_ECUBE_80FTR902".IudtVisu.SM.b0x1_Manual;
      O     "IDB_FB_ECUBE_80FTR903".IudtVisu.SM.b0x1_Manual;
      O     "IDB_FB_ECUBE_80FTR904".IudtVisu.SM.b0x1_Manual;
      O     "IDB_FB_ECUBE_80FTR905".IudtVisu.SM.b0x1_Manual;
      O     "IDB_FB_ECUBE_80FTR906".IudtVisu.SM.b0x1_Manual;
      =     "MANUAL_GR80_R22";

// GROUP 81
      U     "DB_GRP_81".FLA11.SM.ManualMode;
      O     "DB_GRP_81".FLA12.SM.ManualMode;
      O     "DB_GRP_81".FLA13.SM.ManualMode;
      O     "DB_GRP_81".FLA14.SM.ManualMode;
      O     "DB_GRP_81".PP30.SM.ManualMode;
      O     "DB_GRP_81".PP31.SM.ManualMode;
      O     "DB_GRP_81".VA31.SM.ManualMode;
      O     "DB_GRP_81".PP40.SM.ManualMode;
      O     "DB_GRP_81".VA41_M1.SM.ManualMode;
      O     "DB_GRP_81".VA41_M2.SM.ManualMode;
      O     "DB_GRP_81".PP50.SM.ManualMode;
      O     "DB_GRP_81".PP51.SM.ManualMode;
      O     "DB_GRP_81".VA51.SM.ManualMode;
      O     "DB_GRP_81".PP61.SM.ManualMode;
      O     "DB_GRP_81".FIL63_Y1.SM.ManualMode;
      =     "MANUAL_GR81_R27";

      U     "DB_GRP_81".FAN71.SM.ManualMode;
      =     "MANUAL_GR81_R28";

      U     "DB_GRP_81".FAN72.SM.ManualMode;
      =     "MANUAL_GR81_R29";

// GROUP 82
      U     "DB_GRP_82".PP40.SM.ManualMode;
      O     "DB_GRP_82".VA41.SM.ManualMode;
      O     "DB_GRP_82".FAN91.SM.ManualMode;
      O     "DB_GRP_82".FAN92.SM.ManualMode;
      =     "MANUAL_GR82";

// GROUP 83
      U     "DB_GRP_83".PP50.SM.ManualMode;
      O     "DB_GRP_83".PP51.SM.ManualMode;
      O     "DB_GRP_83".VA51.SM.ManualMode;
      O     "DB_GRP_83".FAN91.SM.ManualMode;
      =     "MANUAL_GR83";
NETWORK
TITLE =SET START-UP PARAMETERS
//********************************************************************************
//
//                 SET START UP PARAMETERS (FILLING) FOR E-CUBES
//
//********************************************************************************
//

// E-CUBES 800FTR600
//      L     2.350000e+002
//      T     "IDB_FB_ECUBE_80FTR601".IudtVisu.PV.r9_Cdmax_Cube
//      T     "IDB_FB_ECUBE_80FTR602".IudtVisu.PV.r9_Cdmax_Cube
//      T     "IDB_FB_ECUBE_80FTR603".IudtVisu.PV.r9_Cdmax_Cube
//      T     "IDB_FB_ECUBE_80FTR604".IudtVisu.PV.r9_Cdmax_Cube
//      T     "IDB_FB_ECUBE_80FTR605".IudtVisu.PV.r9_Cdmax_Cube
//      T     "IDB_FB_ECUBE_80FTR606".IudtVisu.PV.r9_Cdmax_Cube
//      T     "IDB_FB_ECUBE_80FTR607".IudtVisu.PV.r9_Cdmax_Cube
//      T     "IDB_FB_ECUBE_80FTR608".IudtVisu.PV.r9_Cdmax_Cube
//      T     "IDB_FB_ECUBE_80FTR609".IudtVisu.PV.r9_Cdmax_Cube
//      T     "IDB_FB_ECUBE_80FTR610".IudtVisu.PV.r9_Cdmax_Cube
//      T     "IDB_FB_ECUBE_80FTR611".IudtVisu.PV.r9_Cdmax_Cube
//      T     "IDB_FB_ECUBE_80FTR612".IudtVisu.PV.r9_Cdmax_Cube
//      T     "IDB_FB_ECUBE_80FTR613".IudtVisu.PV.r9_Cdmax_Cube
//      T     "IDB_FB_ECUBE_80FTR614".IudtVisu.PV.r9_Cdmax_Cube
//      T     "IDB_FB_ECUBE_80FTR615".IudtVisu.PV.r9_Cdmax_Cube
//      T     "IDB_FB_ECUBE_80FTR616".IudtVisu.PV.r9_Cdmax_Cube
//      T     "IDB_FB_ECUBE_80FTR617".IudtVisu.PV.r9_Cdmax_Cube
//      T     "IDB_FB_ECUBE_80FTR618".IudtVisu.PV.r9_Cdmax_Cube

// E-CUBES 800FTR800
//      L     2.350000e+002
//      T     "IDB_FB_ECUBE_80FTR801".IudtVisu.PV.r9_Cdmax_Cube
//      T     "IDB_FB_ECUBE_80FTR802".IudtVisu.PV.r9_Cdmax_Cube
//      T     "IDB_FB_ECUBE_80FTR803".IudtVisu.PV.r9_Cdmax_Cube
//      T     "IDB_FB_ECUBE_80FTR804".IudtVisu.PV.r9_Cdmax_Cube
//      T     "IDB_FB_ECUBE_80FTR805".IudtVisu.PV.r9_Cdmax_Cube
//      T     "IDB_FB_ECUBE_80FTR806".IudtVisu.PV.r9_Cdmax_Cube
//      T     "IDB_FB_ECUBE_80FTR807".IudtVisu.PV.r9_Cdmax_Cube
//      T     "IDB_FB_ECUBE_80FTR808".IudtVisu.PV.r9_Cdmax_Cube
//      T     "IDB_FB_ECUBE_80FTR809".IudtVisu.PV.r9_Cdmax_Cube
//      T     "IDB_FB_ECUBE_80FTR810".IudtVisu.PV.r9_Cdmax_Cube

// E-CUBES 800FTR900
//      L     2.350000e+002
//      T     "IDB_FB_ECUBE_80FTR901".IudtVisu.PV.r9_Cdmax_Cube
//      T     "IDB_FB_ECUBE_80FTR902".IudtVisu.PV.r9_Cdmax_Cube
//      T     "IDB_FB_ECUBE_80FTR903".IudtVisu.PV.r9_Cdmax_Cube
//      T     "IDB_FB_ECUBE_80FTR904".IudtVisu.PV.r9_Cdmax_Cube
//      T     "IDB_FB_ECUBE_80FTR905".IudtVisu.PV.r9_Cdmax_Cube
//      T     "IDB_FB_ECUBE_80FTR906".IudtVisu.PV.r9_Cdmax_Cube




      NOP   0;
NETWORK
TITLE =********** END CYCLE OF PRIMER BOOTH *************

NETWORK
TITLE =FIRE ALARM - CHECK POSITION OF FLAPS

      U     "DB_GRP_80".FLA02.SM.Close;
      U     "80FTR600_FLAPS_CLOSED";
      U     "80FTR800_FLAPS_CLOSED";
      U     "80FTR900_FLAPS_CLOSED";
      U     "DB_GRP_80".FLA60.SM.Close;
      U     "DB_GRP_80".FLA80.SM.Close;
      U     "DB_GRP_80".FLA90.SM.Close;
      U     "DB_GRP_80".FLA97.SM.Close;
      U     "DB_GRP_80".FLA97_M2.SM.Close;
      U     "DB_GRP_84".FLA11.SM.Close;
      U     "DB_GRP_81".FLA11.SM.Close;
      U     "DB_GRP_81".FLA12.SM.Close;
      U     "DB_GRP_81".FLA13.SM.Close;
      U     "DB_GRP_81".FLA14.SM.Close;
      =     "S_FLAPS_CLOSED_BOOTH";
NETWORK
TITLE =END

END_FUNCTION

